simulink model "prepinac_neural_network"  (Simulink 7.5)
settings: Solver=ode45  StartTime=0.0  StopTime=20  FixedStep=1  MaxStep=1  RelTol=1e-3
libraries: neural x26, commutil2 x24, dspmtrx3 x22, simulink x21
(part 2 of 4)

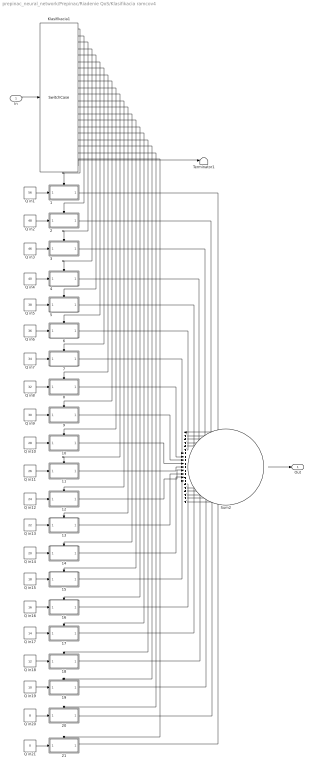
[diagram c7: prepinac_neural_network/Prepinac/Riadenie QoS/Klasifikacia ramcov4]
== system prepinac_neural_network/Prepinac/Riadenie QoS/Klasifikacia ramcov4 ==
  In : Inport  OutDataType=sfix(16)  OutScaling=2^0
  1 : Subsystem  TreatAsAtomicUnit=on
  10 : Subsystem  TreatAsAtomicUnit=on
  11 : Subsystem  TreatAsAtomicUnit=on
  12 : Subsystem  TreatAsAtomicUnit=on
  13 : Subsystem  TreatAsAtomicUnit=on
  14 : Subsystem  TreatAsAtomicUnit=on
  15 : Subsystem  TreatAsAtomicUnit=on
  16 : Subsystem  TreatAsAtomicUnit=on
  17 : Subsystem  TreatAsAtomicUnit=on
  18 : Subsystem  TreatAsAtomicUnit=on
  19 : Subsystem  TreatAsAtomicUnit=on
  2 : Subsystem  TreatAsAtomicUnit=on
  20 : Subsystem  TreatAsAtomicUnit=on
  21 : Subsystem  TreatAsAtomicUnit=on
  3 : Subsystem  TreatAsAtomicUnit=on
  4 : Subsystem  TreatAsAtomicUnit=on
  5 : Subsystem  TreatAsAtomicUnit=on
  6 : Subsystem  TreatAsAtomicUnit=on
  7 : Subsystem  TreatAsAtomicUnit=on
  8 : Subsystem  TreatAsAtomicUnit=on
  9 : Subsystem  TreatAsAtomicUnit=on
  Klasifikacia1 : SwitchCase  CaseConditions={0,8,10,12,14,16,18,20,22,24,26,28,30,32,34,36,38,40,46,48,56}
  Q in1 : Constant  Value=56  VectorParams1D=off  OutDataTypeMode=double  OutDataType=sfix(16)  OutScaling=2^0  OutDataTypeStr=double  SampleTime=-1
  Q in10 : Constant  Value=28  VectorParams1D=off  OutDataTypeMode=double  OutDataType=sfix(16)  OutScaling=2^0  OutDataTypeStr=double  SampleTime=-1
  Q in11 : Constant  Value=26  VectorParams1D=off  OutDataTypeMode=double  OutDataType=sfix(16)  OutScaling=2^0  OutDataTypeStr=double  SampleTime=-1
  Q in12 : Constant  Value=24  VectorParams1D=off  OutDataTypeMode=double  OutDataType=sfix(16)  OutScaling=2^0  OutDataTypeStr=double  SampleTime=-1
  Q in13 : Constant  Value=22  VectorParams1D=off  OutDataTypeMode=double  OutDataType=sfix(16)  OutScaling=2^0  OutDataTypeStr=double  SampleTime=-1
  Q in14 : Constant  Value=20  VectorParams1D=off  OutDataTypeMode=double  OutDataType=sfix(16)  OutScaling=2^0  OutDataTypeStr=double  SampleTime=-1
  Q in15 : Constant  Value=18  VectorParams1D=off  OutDataTypeMode=double  OutDataType=sfix(16)  OutScaling=2^0  OutDataTypeStr=double  SampleTime=-1
  Q in16 : Constant  Value=16  VectorParams1D=off  OutDataTypeMode=double  OutDataType=sfix(16)  OutScaling=2^0  OutDataTypeStr=double  SampleTime=-1
  Q in17 : Constant  Value=14  VectorParams1D=off  OutDataTypeMode=double  OutDataType=sfix(16)  OutScaling=2^0  OutDataTypeStr=double  SampleTime=-1
  Q in18 : Constant  Value=12  VectorParams1D=off  OutDataTypeMode=double  OutDataType=sfix(16)  OutScaling=2^0  OutDataTypeStr=double  SampleTime=-1
  Q in19 : Constant  Value=10  VectorParams1D=off  OutDataTypeMode=double  OutDataType=sfix(16)  OutScaling=2^0  OutDataTypeStr=double  SampleTime=-1
  Q in2 : Constant  Value=48  VectorParams1D=off  OutDataTypeMode=double  OutDataType=sfix(16)  OutScaling=2^0  OutDataTypeStr=double  SampleTime=-1
  Q in20 : Constant  Value=8  VectorParams1D=off  OutDataTypeMode=double  OutDataType=sfix(16)  OutScaling=2^0  OutDataTypeStr=double  SampleTime=-1
  Q in21 : Constant  Value=0  VectorParams1D=off  OutDataTypeMode=double  OutDataType=sfix(16)  OutScaling=2^0  OutDataTypeStr=double  SampleTime=-1
  Q in3 : Constant  Value=46  VectorParams1D=off  OutDataTypeMode=double  OutDataType=sfix(16)  OutScaling=2^0  OutDataTypeStr=double  SampleTime=-1
  Q in4 : Constant  Value=40  VectorParams1D=off  OutDataTypeMode=double  OutDataType=sfix(16)  OutScaling=2^0  OutDataTypeStr=double  SampleTime=-1
  Q in5 : Constant  Value=38  VectorParams1D=off  OutDataTypeMode=double  OutDataType=sfix(16)  OutScaling=2^0  OutDataTypeStr=double  SampleTime=-1
  Q in6 : Constant  Value=36  VectorParams1D=off  OutDataTypeMode=double  OutDataType=sfix(16)  OutScaling=2^0  OutDataTypeStr=double  SampleTime=-1
  Q in7 : Constant  Value=34  VectorParams1D=off  OutDataTypeMode=double  OutDataType=sfix(16)  OutScaling=2^0  OutDataTypeStr=double  SampleTime=-1
  Q in8 : Constant  Value=32  VectorParams1D=off  OutDataTypeMode=double  OutDataType=sfix(16)  OutScaling=2^0  OutDataTypeStr=double  SampleTime=-1
  Q in9 : Constant  Value=30  VectorParams1D=off  OutDataTypeMode=double  OutDataType=sfix(16)  OutScaling=2^0  OutDataTypeStr=double  SampleTime=-1
  Sum2 : Sum  Inputs=|+++++++++++++++++++++  OutDataType=sfix(16)  OutScaling=2^0
  Terminator1 : Terminator
  Out : Outport  OutDataType=sfix(16)  OutScaling=2^0
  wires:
  19/1(Out1) -> Sum2/19
  Klasifikacia1/22 -> Terminator1/1
  Sum2/1 -> Out/1
  Klasifikacia1/21 -> 21/Action
  Klasifikacia1/20 -> 20/Action
  Klasifikacia1/19 -> 19/Action
  Klasifikacia1/18 -> 18/Action
  Klasifikacia1/17 -> 17/Action
  Klasifikacia1/16 -> 16/Action
  Klasifikacia1/15 -> 15/Action
  Klasifikacia1/14 -> 14/Action
  Klasifikacia1/13 -> 13/Action
  Klasifikacia1/12 -> 12/Action
  Klasifikacia1/11 -> 11/Action
  Klasifikacia1/10 -> 10/Action
  Klasifikacia1/9 -> 9/Action
  Klasifikacia1/8 -> 8/Action
  Klasifikacia1/7 -> 7/Action
  Klasifikacia1/6 -> 6/Action
  Klasifikacia1/5 -> 5/Action
  Klasifikacia1/4 -> 4/Action
  Klasifikacia1/3 -> 3/Action
  Klasifikacia1/2 -> 2/Action
  Klasifikacia1/1 -> 1/Action
  In/1 -> Klasifikacia1/1
  9/1(Out1) -> Sum2/9
  10/1(Out1) -> Sum2/10
  11/1(Out1) -> Sum2/11
  12/1(Out1) -> Sum2/12
  13/1(Out1) -> Sum2/13
  14/1(Out1) -> Sum2/14
  15/1(Out1) -> Sum2/15
  16/1(Out1) -> Sum2/16
  17/1(Out1) -> Sum2/17
  18/1(Out1) -> Sum2/18
  20/1(Out1) -> Sum2/20
  21/1(Out1) -> Sum2/21
  8/1(Out1) -> Sum2/8
  7/1(Out1) -> Sum2/7
  6/1(Out1) -> Sum2/6
  5/1(Out1) -> Sum2/5
  Q in21/1 -> 21/1(In1)
  Q in20/1 -> 20/1(In1)
  Q in19/1 -> 19/1(In1)
  Q in18/1 -> 18/1(In1)
  Q in17/1 -> 17/1(In1)
  Q in16/1 -> 16/1(In1)
  Q in15/1 -> 15/1(In1)
  Q in14/1 -> 14/1(In1)
  Q in13/1 -> 13/1(In1)
  Q in12/1 -> 12/1(In1)
  Q in11/1 -> 11/1(In1)
  Q in10/1 -> 10/1(In1)
  Q in9/1 -> 9/1(In1)
  Q in8/1 -> 8/1(In1)
  Q in7/1 -> 7/1(In1)
  Q in6/1 -> 6/1(In1)
  Q in5/1 -> 5/1(In1)
  Q in4/1 -> 4/1(In1)
  Q in3/1 -> 3/1(In1)
  Q in2/1 -> 2/1(In1)
  Q in1/1 -> 1/1(In1)
  4/1(Out1) -> Sum2/4
  3/1(Out1) -> Sum2/3
  2/1(Out1) -> Sum2/2
  1/1(Out1) -> Sum2/1

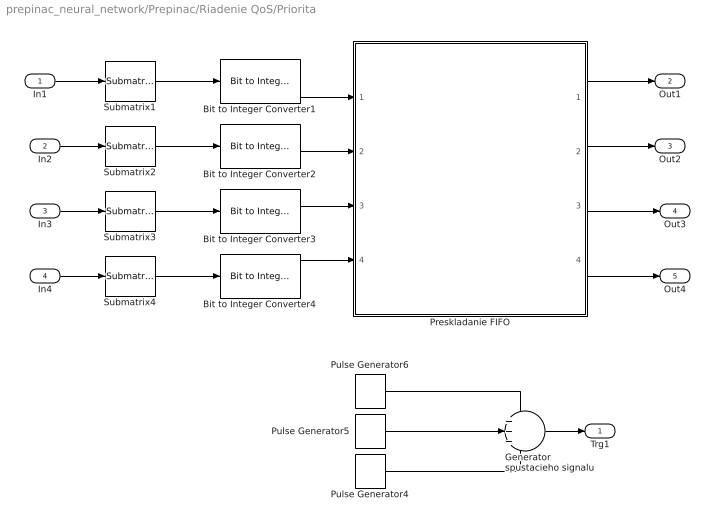
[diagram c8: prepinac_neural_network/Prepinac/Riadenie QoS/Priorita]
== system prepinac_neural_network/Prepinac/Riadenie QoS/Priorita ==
  In1 : Inport  OutDataType=sfix(16)  OutScaling=2^0
  In2 : Inport  Port=2  OutDataType=sfix(16)  OutScaling=2^0
  In3 : Inport  Port=3  OutDataType=sfix(16)  OutScaling=2^0
  In4 : Inport  Port=4  OutDataType=sfix(16)  OutScaling=2^0
  Bit to Integer Converter{1..4} (4 alike) : commutil2/Bit to Integer Converter  nbits=6  bitOrder=MSB first  signedOutputValues=Unsigned  outDtype=double  outDtypeSigned=Inherit via internal rule
  Generator spustacieho signalu : Sum  Inputs=+++  OutDataType=sfix(16)  OutScaling=2^-10
  Preskladanie FIFO : Subsystem
  Pulse Generator4 : DiscretePulseGenerator  PulseType=Time based  Amplitude=3  Period=4  PulseWidth=(1/4)*100  PhaseDelay=4  SampleTime=1
  Pulse Generator5 : DiscretePulseGenerator  PulseType=Time based  Amplitude=2  Period=4  PulseWidth=(1/4)*100  PhaseDelay=3  SampleTime=1
  Pulse Generator6 : DiscretePulseGenerator  PulseType=Time based  Amplitude=1  Period=4  PulseWidth=(1/4)*100  PhaseDelay=2  SampleTime=1
  Submatrix{1..4} (4 alike) : dspmtrx3/Submatrix  RowSpan=All rows  RowStartMode=Index  RowStartIndex=5  RowEndMode=Index  RowEndIndex=12  ColSpan=Range of columns  ColStartMode=Index  ColStartIndex=113  ColEndMode=Index  ColEndIndex=118
  Trg1 : Outport  OutDataType=sfix(16)  OutScaling=2^0
  Out1 : Outport  Port=2  OutDataType=sfix(16)  OutScaling=2^0
  Out2 : Outport  Port=3  OutDataType=sfix(16)  OutScaling=2^0
  Out3 : Outport  Port=4  OutDataType=sfix(16)  OutScaling=2^0
  Out4 : Outport  Port=5  OutDataType=sfix(16)  OutScaling=2^0
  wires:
  In1/1 -> Submatrix1/1
  In2/1 -> Submatrix2/1
  In3/1 -> Submatrix3/1
  In4/1 -> Submatrix4/1
  Submatrix1/1 -> Bit to Integer Converter1/1
  Submatrix2/1 -> Bit to Integer Converter2/1
  Submatrix3/1 -> Bit to Integer Converter3/1
  Submatrix4/1 -> Bit to Integer Converter4/1
  Pulse Generator6/1 -> Generator spustacieho signalu/1
  Pulse Generator5/1 -> Generator spustacieho signalu/2
  Generator spustacieho signalu/1 -> Trg1/1
  Pulse Generator4/1 -> Generator spustacieho signalu/3
  Bit to Integer Converter1/1 -> Preskladanie FIFO/1(In1)
  Bit to Integer Converter3/1 -> Preskladanie FIFO/3(In3)
  Bit to Integer Converter4/1 -> Preskladanie FIFO/4(In4)
  Preskladanie FIFO/1(Out1) -> Out1/1
  Preskladanie FIFO/2(Out2) -> Out2/1
  Preskladanie FIFO/3(Out3) -> Out3/1
  Preskladanie FIFO/4(Out4) -> Out4/1
  Bit to Integer Converter2/1 -> Preskladanie FIFO/2(In2)

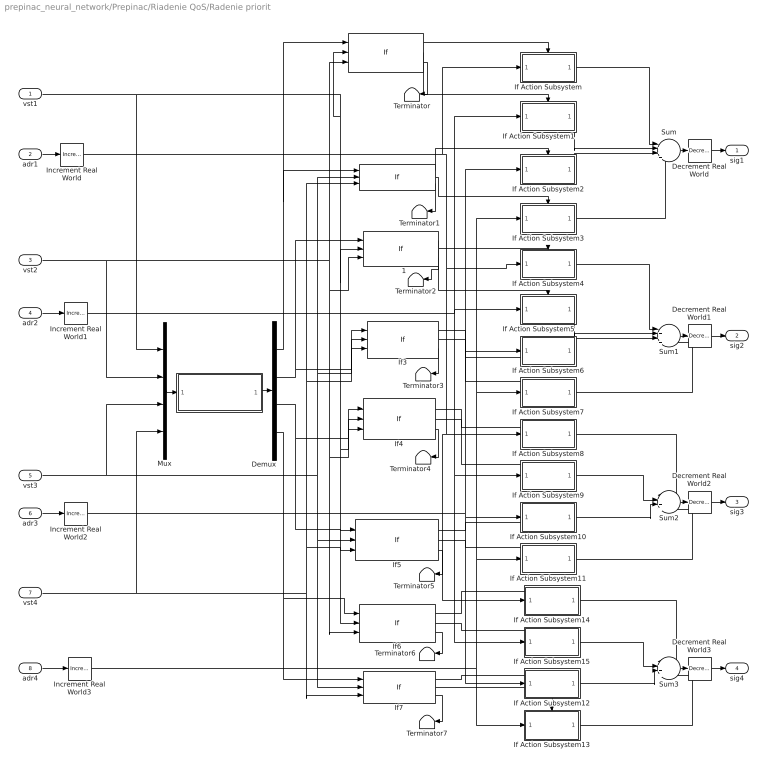
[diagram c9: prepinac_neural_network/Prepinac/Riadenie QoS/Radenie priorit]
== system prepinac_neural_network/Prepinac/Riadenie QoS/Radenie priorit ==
  vst1 : Inport  OutDataType=sfix(16)  OutScaling=2^0
  adr1 : Inport  Port=2  OutDataType=sfix(16)  OutScaling=2^0
  vst2 : Inport  Port=3  OutDataType=sfix(16)  OutScaling=2^0
  adr2 : Inport  Port=4  OutDataType=sfix(16)  OutScaling=2^0
  vst3 : Inport  Port=5  OutDataType=sfix(16)  OutScaling=2^0
  adr3 : Inport  Port=6  OutDataType=sfix(16)  OutScaling=2^0
  vst4 : Inport  Port=7  OutDataType=sfix(16)  OutScaling=2^0
  adr4 : Inport  Port=8  OutDataType=sfix(16)  OutScaling=2^0
  " " : If  NumInputs=3  IfExpression=u1 == u2  ElseIfExpressions=u1 == u3
  "  " : If  NumInputs=3  IfExpression=u1 == u2  ElseIfExpressions=u1 == u3
  "   " : Stateflow chart  TreatAsAtomicUnit=on
  "   1" : If  NumInputs=3  IfExpression=u1 == u2  ElseIfExpressions=u1 == u3
  Decrement Real World{,1..3} (4 alike) : simulink/Additional Math & Discrete/Additional Math: Increment - Decrement/Decrement Real World  SystemSampleTime=-1
  Demux : Demux
  If Action Subsystem : Subsystem  TreatAsAtomicUnit=on
  If Action Subsystem1 : Subsystem  TreatAsAtomicUnit=on
  If Action Subsystem10 : Subsystem  TreatAsAtomicUnit=on
  If Action Subsystem11 : Subsystem  TreatAsAtomicUnit=on
  If Action Subsystem12 : Subsystem  TreatAsAtomicUnit=on
  If Action Subsystem13 : Subsystem  TreatAsAtomicUnit=on
  If Action Subsystem14 : Subsystem  TreatAsAtomicUnit=on
  If Action Subsystem15 : Subsystem  TreatAsAtomicUnit=on
  If Action Subsystem2 : Subsystem  TreatAsAtomicUnit=on
  If Action Subsystem3 : Subsystem  TreatAsAtomicUnit=on
  If Action Subsystem4 : Subsystem  TreatAsAtomicUnit=on
  If Action Subsystem5 : Subsystem  TreatAsAtomicUnit=on
  If Action Subsystem6 : Subsystem  TreatAsAtomicUnit=on
  If Action Subsystem7 : Subsystem  TreatAsAtomicUnit=on
  If Action Subsystem8 : Subsystem  TreatAsAtomicUnit=on
  If Action Subsystem9 : Subsystem  TreatAsAtomicUnit=on
  If{3..7} (5 alike) : If  NumInputs=3  IfExpression=u1 == u2  ElseIfExpressions=u1 == u3
  Increment Real World{,1..3} (4 alike) : simulink/Additional Math & Discrete/Additional Math: Increment - Decrement/Increment Real World  SystemSampleTime=-1
  Mux : Mux
  Sum{,1..3} (4 alike) : Sum  Inputs=|++++  OutDataType=sfix(16)  OutScaling=2^0
  Terminator{,1..7} (8 alike) : Terminator
  sig1 : Outport  OutDataType=sfix(16)  OutScaling=2^0
  sig2 : Outport  Port=2  OutDataType=sfix(16)  OutScaling=2^0
  sig3 : Outport  Port=3  OutDataType=sfix(16)  OutScaling=2^0
  sig4 : Outport  Port=4  OutDataType=sfix(16)  OutScaling=2^0
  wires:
  Mux/1 -> "   "/1(x)
  "   "/1(y) -> Demux/1
  " "/1 -> If Action Subsystem/Action
  " "/2 -> If Action Subsystem1/Action
  adr1/1 -> Increment Real World/1
  adr2/1 -> Increment Real World1/1
  "  "/1 -> If Action Subsystem2/Action
  "  "/2 -> If Action Subsystem3/Action
  adr3/1 -> Increment Real World2/1
  adr4/1 -> Increment Real World3/1
  If Action Subsystem/1(Out1) -> Sum/1
  If Action Subsystem1/1(Out1) -> Sum/2
  If Action Subsystem2/1(Out1) -> Sum/3
  If Action Subsystem3/1(Out1) -> Sum/4
  Sum/1 -> Decrement Real World/1
  Decrement Real World/1 -> sig1/1
  "   1"/1 -> If Action Subsystem4/Action
  "   1"/2 -> If Action Subsystem5/Action
  If3/1 -> If Action Subsystem6/Action
  If3/2 -> If Action Subsystem7/Action
  If Action Subsystem4/1(Out1) -> Sum1/1
  If Action Subsystem5/1(Out1) -> Sum1/2
  If Action Subsystem6/1(Out1) -> Sum1/3
  If Action Subsystem7/1(Out1) -> Sum1/4
  Sum1/1 -> Decrement Real World1/1
  Decrement Real World1/1 -> sig2/1
  If4/1 -> If Action Subsystem8/Action
  If4/2 -> If Action Subsystem9/Action
  If5/1 -> If Action Subsystem10/Action
  If5/2 -> If Action Subsystem11/Action
  If Action Subsystem8/1(Out1) -> Sum2/1
  If Action Subsystem9/1(Out1) -> Sum2/2
  If Action Subsystem10/1(Out1) -> Sum2/3
  If Action Subsystem11/1(Out1) -> Sum2/4
  Sum2/1 -> Decrement Real World2/1
  Decrement Real World2/1 -> sig3/1
  If6/1 -> If Action Subsystem14/Action
  If6/2 -> If Action Subsystem15/Action
  If7/1 -> If Action Subsystem12/Action
  If7/2 -> If Action Subsystem13/Action
  If Action Subsystem14/1(Out1) -> Sum3/1
  If Action Subsystem15/1(Out1) -> Sum3/2
  If Action Subsystem12/1(Out1) -> Sum3/3
  If Action Subsystem13/1(Out1) -> Sum3/4
  Sum3/1 -> Decrement Real World3/1
  Decrement Real World3/1 -> sig4/1
  vst1/1 -> Mux/1, " "/2, "   1"/2, If6/2, If4/2
  vst2/1 -> " "/3, "   1"/3, If6/3, If4/3, Mux/2
  vst3/1 -> "  "/2, If3/2, If5/2, If7/2, Mux/3
  vst4/1 -> "  "/3, If3/3, If5/3, If7/3, Mux/4
  Demux/1 -> " "/1, "  "/1
  Demux/2 -> If3/1, "   1"/1
  Demux/3 -> If4/1, If5/1
  Demux/4 -> If6/1, If7/1
  Increment Real World/1 -> If Action Subsystem/1(In1), If Action Subsystem4/1(In1), If Action Subsystem8/1(In1), If Action Subsystem14/1(In1)
  Increment Real World1/1 -> If Action Subsystem5/1(In1), If Action Subsystem1/1(In1), If Action Subsystem9/1(In1), If Action Subsystem15/1(In1)
  Increment Real World2/1 -> If Action Subsystem2/1(In1), If Action Subsystem6/1(In1), If Action Subsystem10/1(In1), If Action Subsystem12/1(In1)
  Increment Real World3/1 -> If Action Subsystem13/1(In1), If Action Subsystem11/1(In1), If Action Subsystem7/1(In1), If Action Subsystem3/1(In1)
  " "/3 -> Terminator/1
  "  "/3 -> Terminator1/1
  "   1"/3 -> Terminator2/1
  If3/3 -> Terminator3/1
  If4/3 -> Terminator4/1
  If5/3 -> Terminator5/1
  If6/3 -> Terminator6/1
  If7/3 -> Terminator7/1

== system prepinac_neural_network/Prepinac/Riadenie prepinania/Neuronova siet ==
  "x{1}" : Inport  PortDimensions=1  SampleTime=1
  Layer 1 : Subsystem
  Layer 2 : Subsystem
  Process Input 1 : Subsystem
  Process Output 1 : Subsystem
  "y{1}" : Outport  InitialOutput=0
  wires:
  "x{1}"/1 -> Process Input 1/1(x)
  Process Output 1/1(y) -> "y{1}"/1
  Process Input 1/1(p) -> Layer 1/1("p{1}")
  Layer 1/1("a{1}") -> [feedback1]
  [feedback1] -> Layer 2/1("a{1} ")
  Layer 2/1("a{2}") -> Process Output 1/1(a)

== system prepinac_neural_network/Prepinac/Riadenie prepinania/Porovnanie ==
  Vstup : Inport  OutDataType=sfix(16)  OutScaling=2^0
  Abs : Abs
  Porovnani4 : simulink/Logic and Bit Operations/Compare To Constant  SystemSampleTime=-1  relop=>=  const=0.1  LogicOutDataTypeMode=boolean  ZeroCross=off
  Vystup : Outport  OutDataType=sfix(16)  OutScaling=2^0
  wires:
  Abs/1 -> Porovnani4/1
  Porovnani4/1 -> Vystup/1
  Vstup/1 -> Abs/1

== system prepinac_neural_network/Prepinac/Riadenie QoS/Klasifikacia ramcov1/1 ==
  In1 : Inport  OutDataType=sfix(16)  OutScaling=2^0
  Action Port : ActionPort  ActionType=case
  Out1 : Outport  OutDataType=sfix(16)  OutScaling=2^0
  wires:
  In1/1 -> Out1/1

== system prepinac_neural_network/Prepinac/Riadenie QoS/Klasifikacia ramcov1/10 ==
  In1 : Inport  OutDataType=sfix(16)  OutScaling=2^0
  Action Port : ActionPort  ActionType=case
  Out1 : Outport  OutDataType=sfix(16)  OutScaling=2^0
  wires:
  In1/1 -> Out1/1

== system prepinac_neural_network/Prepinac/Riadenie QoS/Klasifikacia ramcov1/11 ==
  In1 : Inport  OutDataType=sfix(16)  OutScaling=2^0
  Action Port : ActionPort  ActionType=case
  Out1 : Outport  OutDataType=sfix(16)  OutScaling=2^0
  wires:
  In1/1 -> Out1/1

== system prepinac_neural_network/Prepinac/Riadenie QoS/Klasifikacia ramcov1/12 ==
  In1 : Inport  OutDataType=sfix(16)  OutScaling=2^0
  Action Port : ActionPort  ActionType=case
  Out1 : Outport  OutDataType=sfix(16)  OutScaling=2^0
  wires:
  In1/1 -> Out1/1

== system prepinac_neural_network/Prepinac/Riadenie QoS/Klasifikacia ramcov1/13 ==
  In1 : Inport  OutDataType=sfix(16)  OutScaling=2^0
  Action Port : ActionPort  ActionType=case
  Out1 : Outport  OutDataType=sfix(16)  OutScaling=2^0
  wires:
  In1/1 -> Out1/1

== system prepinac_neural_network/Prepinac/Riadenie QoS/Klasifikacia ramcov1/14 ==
  In1 : Inport  OutDataType=sfix(16)  OutScaling=2^0
  Action Port : ActionPort  ActionType=case
  Out1 : Outport  OutDataType=sfix(16)  OutScaling=2^0
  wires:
  In1/1 -> Out1/1

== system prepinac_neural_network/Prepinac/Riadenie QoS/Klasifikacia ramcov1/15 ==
  In1 : Inport  OutDataType=sfix(16)  OutScaling=2^0
  Action Port : ActionPort  ActionType=case
  Out1 : Outport  OutDataType=sfix(16)  OutScaling=2^0
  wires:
  In1/1 -> Out1/1

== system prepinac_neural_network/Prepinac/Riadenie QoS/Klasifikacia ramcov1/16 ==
  In1 : Inport  OutDataType=sfix(16)  OutScaling=2^0
  Action Port : ActionPort  ActionType=case
  Out1 : Outport  OutDataType=sfix(16)  OutScaling=2^0
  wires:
  In1/1 -> Out1/1

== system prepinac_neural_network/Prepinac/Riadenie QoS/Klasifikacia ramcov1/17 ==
  In1 : Inport  OutDataType=sfix(16)  OutScaling=2^0
  Action Port : ActionPort  ActionType=case
  Out1 : Outport  OutDataType=sfix(16)  OutScaling=2^0
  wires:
  In1/1 -> Out1/1

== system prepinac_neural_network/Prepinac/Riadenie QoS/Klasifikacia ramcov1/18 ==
  In1 : Inport  OutDataType=sfix(16)  OutScaling=2^0
  Action Port : ActionPort  ActionType=case
  Out1 : Outport  OutDataType=sfix(16)  OutScaling=2^0
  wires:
  In1/1 -> Out1/1

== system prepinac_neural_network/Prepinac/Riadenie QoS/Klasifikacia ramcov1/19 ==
  In1 : Inport  OutDataType=sfix(16)  OutScaling=2^0
  Action Port : ActionPort  ActionType=case
  Out1 : Outport  OutDataType=sfix(16)  OutScaling=2^0
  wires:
  In1/1 -> Out1/1

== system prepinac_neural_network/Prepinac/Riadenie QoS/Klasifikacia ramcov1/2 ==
  In1 : Inport  OutDataType=sfix(16)  OutScaling=2^0
  Action Port : ActionPort  ActionType=case
  Out1 : Outport  OutDataType=sfix(16)  OutScaling=2^0
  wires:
  In1/1 -> Out1/1

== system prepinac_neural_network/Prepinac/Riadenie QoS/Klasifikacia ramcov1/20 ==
  In1 : Inport  OutDataType=sfix(16)  OutScaling=2^0
  Action Port : ActionPort  ActionType=case
  Out1 : Outport  OutDataType=sfix(16)  OutScaling=2^0
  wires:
  In1/1 -> Out1/1

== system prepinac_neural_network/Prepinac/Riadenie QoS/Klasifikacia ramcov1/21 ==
  In1 : Inport  OutDataType=sfix(16)  OutScaling=2^0
  Action Port : ActionPort  ActionType=case
  Out1 : Outport  OutDataType=sfix(16)  OutScaling=2^0
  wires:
  In1/1 -> Out1/1

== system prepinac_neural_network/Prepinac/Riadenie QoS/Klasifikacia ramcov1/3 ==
  In1 : Inport  OutDataType=sfix(16)  OutScaling=2^0
  Action Port : ActionPort  ActionType=case
  Out1 : Outport  OutDataType=sfix(16)  OutScaling=2^0
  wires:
  In1/1 -> Out1/1

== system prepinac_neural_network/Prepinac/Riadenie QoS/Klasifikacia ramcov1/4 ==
  In1 : Inport  OutDataType=sfix(16)  OutScaling=2^0
  Action Port : ActionPort  ActionType=case
  Out1 : Outport  OutDataType=sfix(16)  OutScaling=2^0
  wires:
  In1/1 -> Out1/1

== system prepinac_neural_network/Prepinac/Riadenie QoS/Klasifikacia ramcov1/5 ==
  In1 : Inport  OutDataType=sfix(16)  OutScaling=2^0
  Action Port : ActionPort  ActionType=case
  Out1 : Outport  OutDataType=sfix(16)  OutScaling=2^0
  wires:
  In1/1 -> Out1/1

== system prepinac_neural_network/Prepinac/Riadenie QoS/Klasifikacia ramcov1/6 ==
  In1 : Inport  OutDataType=sfix(16)  OutScaling=2^0
  Action Port : ActionPort  ActionType=case
  Out1 : Outport  OutDataType=sfix(16)  OutScaling=2^0
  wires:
  In1/1 -> Out1/1

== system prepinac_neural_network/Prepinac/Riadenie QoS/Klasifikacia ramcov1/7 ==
  In1 : Inport  OutDataType=sfix(16)  OutScaling=2^0
  Action Port : ActionPort  ActionType=case
  Out1 : Outport  OutDataType=sfix(16)  OutScaling=2^0
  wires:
  In1/1 -> Out1/1

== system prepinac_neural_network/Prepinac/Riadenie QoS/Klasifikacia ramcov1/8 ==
  In1 : Inport  OutDataType=sfix(16)  OutScaling=2^0
  Action Port : ActionPort  ActionType=case
  Out1 : Outport  OutDataType=sfix(16)  OutScaling=2^0
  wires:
  In1/1 -> Out1/1

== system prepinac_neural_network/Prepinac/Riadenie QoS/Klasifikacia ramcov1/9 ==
  In1 : Inport  OutDataType=sfix(16)  OutScaling=2^0
  Action Port : ActionPort  ActionType=case
  Out1 : Outport  OutDataType=sfix(16)  OutScaling=2^0
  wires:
  In1/1 -> Out1/1

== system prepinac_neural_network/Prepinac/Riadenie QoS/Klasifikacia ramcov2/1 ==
  In1 : Inport  OutDataType=sfix(16)  OutScaling=2^0
  Action Port : ActionPort  ActionType=case
  Out1 : Outport  OutDataType=sfix(16)  OutScaling=2^0
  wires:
  In1/1 -> Out1/1

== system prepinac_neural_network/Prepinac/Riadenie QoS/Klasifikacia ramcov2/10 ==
  In1 : Inport  OutDataType=sfix(16)  OutScaling=2^0
  Action Port : ActionPort  ActionType=case
  Out1 : Outport  OutDataType=sfix(16)  OutScaling=2^0
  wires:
  In1/1 -> Out1/1

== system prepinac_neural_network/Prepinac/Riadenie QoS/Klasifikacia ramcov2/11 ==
  In1 : Inport  OutDataType=sfix(16)  OutScaling=2^0
  Action Port : ActionPort  ActionType=case
  Out1 : Outport  OutDataType=sfix(16)  OutScaling=2^0
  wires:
  In1/1 -> Out1/1

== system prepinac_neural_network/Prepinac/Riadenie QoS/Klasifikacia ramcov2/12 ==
  In1 : Inport  OutDataType=sfix(16)  OutScaling=2^0
  Action Port : ActionPort  ActionType=case
  Out1 : Outport  OutDataType=sfix(16)  OutScaling=2^0
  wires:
  In1/1 -> Out1/1

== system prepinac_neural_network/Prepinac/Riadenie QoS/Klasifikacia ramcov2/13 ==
  In1 : Inport  OutDataType=sfix(16)  OutScaling=2^0
  Action Port : ActionPort  ActionType=case
  Out1 : Outport  OutDataType=sfix(16)  OutScaling=2^0
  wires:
  In1/1 -> Out1/1

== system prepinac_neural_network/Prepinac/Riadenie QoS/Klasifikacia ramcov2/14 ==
  In1 : Inport  OutDataType=sfix(16)  OutScaling=2^0
  Action Port : ActionPort  ActionType=case
  Out1 : Outport  OutDataType=sfix(16)  OutScaling=2^0
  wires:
  In1/1 -> Out1/1

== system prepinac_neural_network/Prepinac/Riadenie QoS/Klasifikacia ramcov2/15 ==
  In1 : Inport  OutDataType=sfix(16)  OutScaling=2^0
  Action Port : ActionPort  ActionType=case
  Out1 : Outport  OutDataType=sfix(16)  OutScaling=2^0
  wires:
  In1/1 -> Out1/1

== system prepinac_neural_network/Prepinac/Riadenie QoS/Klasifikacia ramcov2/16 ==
  In1 : Inport  OutDataType=sfix(16)  OutScaling=2^0
  Action Port : ActionPort  ActionType=case
  Out1 : Outport  OutDataType=sfix(16)  OutScaling=2^0
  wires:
  In1/1 -> Out1/1

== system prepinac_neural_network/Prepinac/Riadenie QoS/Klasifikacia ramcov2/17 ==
  In1 : Inport  OutDataType=sfix(16)  OutScaling=2^0
  Action Port : ActionPort  ActionType=case
  Out1 : Outport  OutDataType=sfix(16)  OutScaling=2^0
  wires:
  In1/1 -> Out1/1

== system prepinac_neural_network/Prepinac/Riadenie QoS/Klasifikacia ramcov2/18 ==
  In1 : Inport  OutDataType=sfix(16)  OutScaling=2^0
  Action Port : ActionPort  ActionType=case
  Out1 : Outport  OutDataType=sfix(16)  OutScaling=2^0
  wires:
  In1/1 -> Out1/1

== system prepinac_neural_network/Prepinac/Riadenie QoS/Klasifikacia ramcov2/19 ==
  In1 : Inport  OutDataType=sfix(16)  OutScaling=2^0
  Action Port : ActionPort  ActionType=case
  Out1 : Outport  OutDataType=sfix(16)  OutScaling=2^0
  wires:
  In1/1 -> Out1/1

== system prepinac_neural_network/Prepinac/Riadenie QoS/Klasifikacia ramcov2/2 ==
  In1 : Inport  OutDataType=sfix(16)  OutScaling=2^0
  Action Port : ActionPort  ActionType=case
  Out1 : Outport  OutDataType=sfix(16)  OutScaling=2^0
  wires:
  In1/1 -> Out1/1

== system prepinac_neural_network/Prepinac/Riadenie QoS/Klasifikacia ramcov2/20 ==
  In1 : Inport  OutDataType=sfix(16)  OutScaling=2^0
  Action Port : ActionPort  ActionType=case
  Out1 : Outport  OutDataType=sfix(16)  OutScaling=2^0
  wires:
  In1/1 -> Out1/1

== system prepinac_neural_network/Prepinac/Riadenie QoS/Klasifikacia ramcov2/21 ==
  In1 : Inport  OutDataType=sfix(16)  OutScaling=2^0
  Action Port : ActionPort  ActionType=case
  Out1 : Outport  OutDataType=sfix(16)  OutScaling=2^0
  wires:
  In1/1 -> Out1/1

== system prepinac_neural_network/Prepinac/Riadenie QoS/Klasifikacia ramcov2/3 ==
  In1 : Inport  OutDataType=sfix(16)  OutScaling=2^0
  Action Port : ActionPort  ActionType=case
  Out1 : Outport  OutDataType=sfix(16)  OutScaling=2^0
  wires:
  In1/1 -> Out1/1

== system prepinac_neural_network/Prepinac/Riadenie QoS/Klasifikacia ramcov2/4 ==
  In1 : Inport  OutDataType=sfix(16)  OutScaling=2^0
  Action Port : ActionPort  ActionType=case
  Out1 : Outport  OutDataType=sfix(16)  OutScaling=2^0
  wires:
  In1/1 -> Out1/1

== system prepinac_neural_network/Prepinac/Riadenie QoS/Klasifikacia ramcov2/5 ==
  In1 : Inport  OutDataType=sfix(16)  OutScaling=2^0
  Action Port : ActionPort  ActionType=case
  Out1 : Outport  OutDataType=sfix(16)  OutScaling=2^0
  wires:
  In1/1 -> Out1/1

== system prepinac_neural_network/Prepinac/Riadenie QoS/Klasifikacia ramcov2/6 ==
  In1 : Inport  OutDataType=sfix(16)  OutScaling=2^0
  Action Port : ActionPort  ActionType=case
  Out1 : Outport  OutDataType=sfix(16)  OutScaling=2^0
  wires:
  In1/1 -> Out1/1

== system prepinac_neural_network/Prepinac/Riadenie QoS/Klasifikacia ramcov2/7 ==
  In1 : Inport  OutDataType=sfix(16)  OutScaling=2^0
  Action Port : ActionPort  ActionType=case
  Out1 : Outport  OutDataType=sfix(16)  OutScaling=2^0
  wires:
  In1/1 -> Out1/1

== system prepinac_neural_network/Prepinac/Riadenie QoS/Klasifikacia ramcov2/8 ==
  In1 : Inport  OutDataType=sfix(16)  OutScaling=2^0
  Action Port : ActionPort  ActionType=case
  Out1 : Outport  OutDataType=sfix(16)  OutScaling=2^0
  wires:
  In1/1 -> Out1/1

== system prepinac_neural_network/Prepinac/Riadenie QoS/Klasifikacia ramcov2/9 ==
  In1 : Inport  OutDataType=sfix(16)  OutScaling=2^0
  Action Port : ActionPort  ActionType=case
  Out1 : Outport  OutDataType=sfix(16)  OutScaling=2^0
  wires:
  In1/1 -> Out1/1

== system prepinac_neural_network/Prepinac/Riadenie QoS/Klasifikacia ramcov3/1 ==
  In1 : Inport  OutDataType=sfix(16)  OutScaling=2^0
  Action Port : ActionPort  ActionType=case
  Out1 : Outport  OutDataType=sfix(16)  OutScaling=2^0
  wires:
  In1/1 -> Out1/1

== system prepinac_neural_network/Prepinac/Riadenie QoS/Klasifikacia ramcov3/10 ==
  In1 : Inport  OutDataType=sfix(16)  OutScaling=2^0
  Action Port : ActionPort  ActionType=case
  Out1 : Outport  OutDataType=sfix(16)  OutScaling=2^0
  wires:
  In1/1 -> Out1/1

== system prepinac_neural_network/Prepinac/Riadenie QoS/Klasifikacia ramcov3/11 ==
  In1 : Inport  OutDataType=sfix(16)  OutScaling=2^0
  Action Port : ActionPort  ActionType=case
  Out1 : Outport  OutDataType=sfix(16)  OutScaling=2^0
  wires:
  In1/1 -> Out1/1

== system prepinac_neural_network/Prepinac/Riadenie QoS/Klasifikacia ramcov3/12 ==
  In1 : Inport  OutDataType=sfix(16)  OutScaling=2^0
  Action Port : ActionPort  ActionType=case
  Out1 : Outport  OutDataType=sfix(16)  OutScaling=2^0
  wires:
  In1/1 -> Out1/1

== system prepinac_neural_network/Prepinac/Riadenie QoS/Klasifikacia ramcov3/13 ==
  In1 : Inport  OutDataType=sfix(16)  OutScaling=2^0
  Action Port : ActionPort  ActionType=case
  Out1 : Outport  OutDataType=sfix(16)  OutScaling=2^0
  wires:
  In1/1 -> Out1/1

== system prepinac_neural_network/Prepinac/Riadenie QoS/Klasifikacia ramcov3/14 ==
  In1 : Inport  OutDataType=sfix(16)  OutScaling=2^0
  Action Port : ActionPort  ActionType=case
  Out1 : Outport  OutDataType=sfix(16)  OutScaling=2^0
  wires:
  In1/1 -> Out1/1

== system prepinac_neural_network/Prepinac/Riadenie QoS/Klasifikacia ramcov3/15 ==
  In1 : Inport  OutDataType=sfix(16)  OutScaling=2^0
  Action Port : ActionPort  ActionType=case
  Out1 : Outport  OutDataType=sfix(16)  OutScaling=2^0
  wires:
  In1/1 -> Out1/1

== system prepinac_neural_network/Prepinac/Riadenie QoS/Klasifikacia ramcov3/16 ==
  In1 : Inport  OutDataType=sfix(16)  OutScaling=2^0
  Action Port : ActionPort  ActionType=case
  Out1 : Outport  OutDataType=sfix(16)  OutScaling=2^0
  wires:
  In1/1 -> Out1/1

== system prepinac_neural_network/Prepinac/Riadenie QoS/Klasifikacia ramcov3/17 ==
  In1 : Inport  OutDataType=sfix(16)  OutScaling=2^0
  Action Port : ActionPort  ActionType=case
  Out1 : Outport  OutDataType=sfix(16)  OutScaling=2^0
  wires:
  In1/1 -> Out1/1

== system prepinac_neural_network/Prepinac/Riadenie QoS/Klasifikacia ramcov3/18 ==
  In1 : Inport  OutDataType=sfix(16)  OutScaling=2^0
  Action Port : ActionPort  ActionType=case
  Out1 : Outport  OutDataType=sfix(16)  OutScaling=2^0
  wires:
  In1/1 -> Out1/1

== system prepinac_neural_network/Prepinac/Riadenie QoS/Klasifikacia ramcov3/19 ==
  In1 : Inport  OutDataType=sfix(16)  OutScaling=2^0
  Action Port : ActionPort  ActionType=case
  Out1 : Outport  OutDataType=sfix(16)  OutScaling=2^0
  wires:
  In1/1 -> Out1/1

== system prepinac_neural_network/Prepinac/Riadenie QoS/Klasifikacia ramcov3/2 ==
  In1 : Inport  OutDataType=sfix(16)  OutScaling=2^0
  Action Port : ActionPort  ActionType=case
  Out1 : Outport  OutDataType=sfix(16)  OutScaling=2^0
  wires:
  In1/1 -> Out1/1

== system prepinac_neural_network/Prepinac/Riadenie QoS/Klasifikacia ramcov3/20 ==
  In1 : Inport  OutDataType=sfix(16)  OutScaling=2^0
  Action Port : ActionPort  ActionType=case
  Out1 : Outport  OutDataType=sfix(16)  OutScaling=2^0
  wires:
  In1/1 -> Out1/1

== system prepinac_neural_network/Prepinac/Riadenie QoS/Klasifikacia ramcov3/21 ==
  In1 : Inport  OutDataType=sfix(16)  OutScaling=2^0
  Action Port : ActionPort  ActionType=case
  Out1 : Outport  OutDataType=sfix(16)  OutScaling=2^0
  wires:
  In1/1 -> Out1/1

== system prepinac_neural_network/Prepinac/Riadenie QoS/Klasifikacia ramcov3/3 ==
  In1 : Inport  OutDataType=sfix(16)  OutScaling=2^0
  Action Port : ActionPort  ActionType=case
  Out1 : Outport  OutDataType=sfix(16)  OutScaling=2^0
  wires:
  In1/1 -> Out1/1

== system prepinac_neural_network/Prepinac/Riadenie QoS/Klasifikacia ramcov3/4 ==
  In1 : Inport  OutDataType=sfix(16)  OutScaling=2^0
  Action Port : ActionPort  ActionType=case
  Out1 : Outport  OutDataType=sfix(16)  OutScaling=2^0
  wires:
  In1/1 -> Out1/1

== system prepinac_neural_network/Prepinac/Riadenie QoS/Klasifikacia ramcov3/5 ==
  In1 : Inport  OutDataType=sfix(16)  OutScaling=2^0
  Action Port : ActionPort  ActionType=case
  Out1 : Outport  OutDataType=sfix(16)  OutScaling=2^0
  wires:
  In1/1 -> Out1/1

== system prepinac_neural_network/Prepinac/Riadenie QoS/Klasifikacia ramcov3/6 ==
  In1 : Inport  OutDataType=sfix(16)  OutScaling=2^0
  Action Port : ActionPort  ActionType=case
  Out1 : Outport  OutDataType=sfix(16)  OutScaling=2^0
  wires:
  In1/1 -> Out1/1

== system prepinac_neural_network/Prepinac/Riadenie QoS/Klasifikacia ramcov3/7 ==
  In1 : Inport  OutDataType=sfix(16)  OutScaling=2^0
  Action Port : ActionPort  ActionType=case
  Out1 : Outport  OutDataType=sfix(16)  OutScaling=2^0
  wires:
  In1/1 -> Out1/1

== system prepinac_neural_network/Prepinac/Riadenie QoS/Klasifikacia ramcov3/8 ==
  In1 : Inport  OutDataType=sfix(16)  OutScaling=2^0
  Action Port : ActionPort  ActionType=case
  Out1 : Outport  OutDataType=sfix(16)  OutScaling=2^0
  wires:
  In1/1 -> Out1/1

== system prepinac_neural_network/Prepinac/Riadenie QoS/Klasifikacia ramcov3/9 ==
  In1 : Inport  OutDataType=sfix(16)  OutScaling=2^0
  Action Port : ActionPort  ActionType=case
  Out1 : Outport  OutDataType=sfix(16)  OutScaling=2^0
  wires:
  In1/1 -> Out1/1

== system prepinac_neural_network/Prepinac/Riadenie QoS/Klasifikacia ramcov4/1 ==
  In1 : Inport  OutDataType=sfix(16)  OutScaling=2^0
  Action Port : ActionPort  ActionType=case
  Out1 : Outport  OutDataType=sfix(16)  OutScaling=2^0
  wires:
  In1/1 -> Out1/1

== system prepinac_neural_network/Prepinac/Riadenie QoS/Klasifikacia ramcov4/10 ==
  In1 : Inport  OutDataType=sfix(16)  OutScaling=2^0
  Action Port : ActionPort  ActionType=case
  Out1 : Outport  OutDataType=sfix(16)  OutScaling=2^0
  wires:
  In1/1 -> Out1/1

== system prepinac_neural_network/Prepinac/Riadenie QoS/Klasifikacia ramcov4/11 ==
  In1 : Inport  OutDataType=sfix(16)  OutScaling=2^0
  Action Port : ActionPort  ActionType=case
  Out1 : Outport  OutDataType=sfix(16)  OutScaling=2^0
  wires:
  In1/1 -> Out1/1

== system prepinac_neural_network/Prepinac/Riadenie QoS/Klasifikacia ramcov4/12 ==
  In1 : Inport  OutDataType=sfix(16)  OutScaling=2^0
  Action Port : ActionPort  ActionType=case
  Out1 : Outport  OutDataType=sfix(16)  OutScaling=2^0
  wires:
  In1/1 -> Out1/1

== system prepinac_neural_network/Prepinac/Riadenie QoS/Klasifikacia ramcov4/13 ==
  In1 : Inport  OutDataType=sfix(16)  OutScaling=2^0
  Action Port : ActionPort  ActionType=case
  Out1 : Outport  OutDataType=sfix(16)  OutScaling=2^0
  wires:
  In1/1 -> Out1/1

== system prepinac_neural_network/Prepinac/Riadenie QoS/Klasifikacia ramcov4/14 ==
  In1 : Inport  OutDataType=sfix(16)  OutScaling=2^0
  Action Port : ActionPort  ActionType=case
  Out1 : Outport  OutDataType=sfix(16)  OutScaling=2^0
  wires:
  In1/1 -> Out1/1

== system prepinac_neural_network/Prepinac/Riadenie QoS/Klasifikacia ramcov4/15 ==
  In1 : Inport  OutDataType=sfix(16)  OutScaling=2^0
  Action Port : ActionPort  ActionType=case
  Out1 : Outport  OutDataType=sfix(16)  OutScaling=2^0
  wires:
  In1/1 -> Out1/1

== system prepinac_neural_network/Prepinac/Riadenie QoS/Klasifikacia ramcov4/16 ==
  In1 : Inport  OutDataType=sfix(16)  OutScaling=2^0
  Action Port : ActionPort  ActionType=case
  Out1 : Outport  OutDataType=sfix(16)  OutScaling=2^0
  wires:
  In1/1 -> Out1/1

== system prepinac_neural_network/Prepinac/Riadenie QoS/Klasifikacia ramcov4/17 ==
  In1 : Inport  OutDataType=sfix(16)  OutScaling=2^0
  Action Port : ActionPort  ActionType=case
  Out1 : Outport  OutDataType=sfix(16)  OutScaling=2^0
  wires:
  In1/1 -> Out1/1

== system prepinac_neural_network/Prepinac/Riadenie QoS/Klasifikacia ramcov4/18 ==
  In1 : Inport  OutDataType=sfix(16)  OutScaling=2^0
  Action Port : ActionPort  ActionType=case
  Out1 : Outport  OutDataType=sfix(16)  OutScaling=2^0
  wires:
  In1/1 -> Out1/1

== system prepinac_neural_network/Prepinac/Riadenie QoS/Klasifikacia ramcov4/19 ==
  In1 : Inport  OutDataType=sfix(16)  OutScaling=2^0
  Action Port : ActionPort  ActionType=case
  Out1 : Outport  OutDataType=sfix(16)  OutScaling=2^0
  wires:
  In1/1 -> Out1/1

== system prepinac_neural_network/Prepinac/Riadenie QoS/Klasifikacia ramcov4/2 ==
  In1 : Inport  OutDataType=sfix(16)  OutScaling=2^0
  Action Port : ActionPort  ActionType=case
  Out1 : Outport  OutDataType=sfix(16)  OutScaling=2^0
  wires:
  In1/1 -> Out1/1

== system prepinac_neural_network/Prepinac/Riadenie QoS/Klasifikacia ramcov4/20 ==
  In1 : Inport  OutDataType=sfix(16)  OutScaling=2^0
  Action Port : ActionPort  ActionType=case
  Out1 : Outport  OutDataType=sfix(16)  OutScaling=2^0
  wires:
  In1/1 -> Out1/1

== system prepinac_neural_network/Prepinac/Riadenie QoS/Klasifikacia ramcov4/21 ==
  In1 : Inport  OutDataType=sfix(16)  OutScaling=2^0
  Action Port : ActionPort  ActionType=case
  Out1 : Outport  OutDataType=sfix(16)  OutScaling=2^0
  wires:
  In1/1 -> Out1/1

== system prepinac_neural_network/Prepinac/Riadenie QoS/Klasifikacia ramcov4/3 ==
  In1 : Inport  OutDataType=sfix(16)  OutScaling=2^0
  Action Port : ActionPort  ActionType=case
  Out1 : Outport  OutDataType=sfix(16)  OutScaling=2^0
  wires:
  In1/1 -> Out1/1

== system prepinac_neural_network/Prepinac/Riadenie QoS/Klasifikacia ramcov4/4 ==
  In1 : Inport  OutDataType=sfix(16)  OutScaling=2^0
  Action Port : ActionPort  ActionType=case
  Out1 : Outport  OutDataType=sfix(16)  OutScaling=2^0
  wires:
  In1/1 -> Out1/1

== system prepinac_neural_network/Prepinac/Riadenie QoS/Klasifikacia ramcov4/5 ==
  In1 : Inport  OutDataType=sfix(16)  OutScaling=2^0
  Action Port : ActionPort  ActionType=case
  Out1 : Outport  OutDataType=sfix(16)  OutScaling=2^0
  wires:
  In1/1 -> Out1/1

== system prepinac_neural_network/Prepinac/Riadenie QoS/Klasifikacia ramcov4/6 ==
  In1 : Inport  OutDataType=sfix(16)  OutScaling=2^0
  Action Port : ActionPort  ActionType=case
  Out1 : Outport  OutDataType=sfix(16)  OutScaling=2^0
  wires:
  In1/1 -> Out1/1

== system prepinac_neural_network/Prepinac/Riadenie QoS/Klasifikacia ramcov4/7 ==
  In1 : Inport  OutDataType=sfix(16)  OutScaling=2^0
  Action Port : ActionPort  ActionType=case
  Out1 : Outport  OutDataType=sfix(16)  OutScaling=2^0
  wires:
  In1/1 -> Out1/1

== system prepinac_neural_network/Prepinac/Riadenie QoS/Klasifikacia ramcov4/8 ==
  In1 : Inport  OutDataType=sfix(16)  OutScaling=2^0
  Action Port : ActionPort  ActionType=case
  Out1 : Outport  OutDataType=sfix(16)  OutScaling=2^0
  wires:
  In1/1 -> Out1/1

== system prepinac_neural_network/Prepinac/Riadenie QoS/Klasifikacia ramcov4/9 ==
  In1 : Inport  OutDataType=sfix(16)  OutScaling=2^0
  Action Port : ActionPort  ActionType=case
  Out1 : Outport  OutDataType=sfix(16)  OutScaling=2^0
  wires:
  In1/1 -> Out1/1
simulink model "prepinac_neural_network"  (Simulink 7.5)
settings: Solver=ode45  StartTime=0.0  StopTime=20  FixedStep=1  MaxStep=1  RelTol=1e-3
libraries: neural x26, commutil2 x24, dspmtrx3 x22, simulink x21
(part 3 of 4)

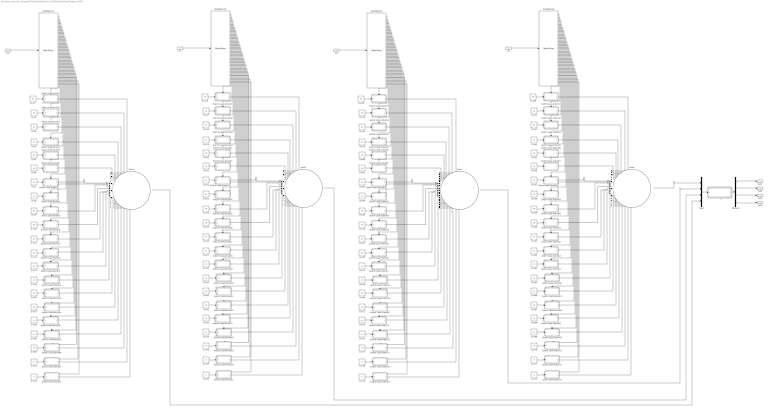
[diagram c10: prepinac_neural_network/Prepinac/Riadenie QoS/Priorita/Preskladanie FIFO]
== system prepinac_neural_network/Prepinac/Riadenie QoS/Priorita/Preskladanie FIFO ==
  In1 : Inport  OutDataType=sfix(16)  OutScaling=2^0
  In2 : Inport  Port=2  OutDataType=sfix(16)  OutScaling=2^0
  In3 : Inport  Port=3  OutDataType=sfix(16)  OutScaling=2^0
  In4 : Inport  Port=4  OutDataType=sfix(16)  OutScaling=2^0
  "     1" : Stateflow chart  TreatAsAtomicUnit=on
  Demux1 : Demux
  Klasifikacia{1..4} (4 alike) : SwitchCase  CaseConditions={0,8,10,12,14,16,18,20,22,24,26,28,30,32,34,36,38,40,46,48,56}  ShowDefaultCase=off
  Mux1 : Mux
  Q in{1,16,43,50} (4 alike) : Constant  Value=56  VectorParams1D=off  OutDataTypeMode=double  OutDataType=sfix(16)  OutScaling=2^0  OutDataTypeStr=double  SampleTime=-1
  Q in{10,25,44,60} (4 alike) : Constant  Value=28  VectorParams1D=off  OutDataTypeMode=double  OutDataType=sfix(16)  OutScaling=2^0  OutDataTypeStr=double  SampleTime=-1
  Q in{11,26,45,61} (4 alike) : Constant  Value=26  VectorParams1D=off  OutDataTypeMode=double  OutDataType=sfix(16)  OutScaling=2^0  OutDataTypeStr=double  SampleTime=-1
  Q in{12,27,46,62} (4 alike) : Constant  Value=24  VectorParams1D=off  OutDataTypeMode=double  OutDataType=sfix(16)  OutScaling=2^0  OutDataTypeStr=double  SampleTime=-1
  Q in{13,28,47,63} (4 alike) : Constant  Value=22  VectorParams1D=off  OutDataTypeMode=double  OutDataType=sfix(16)  OutScaling=2^0  OutDataTypeStr=double  SampleTime=-1
  Q in{14,29,48,64} (4 alike) : Constant  Value=20  VectorParams1D=off  OutDataTypeMode=double  OutDataType=sfix(16)  OutScaling=2^0  OutDataTypeStr=double  SampleTime=-1
  Q in{15,30,49,66} (4 alike) : Constant  Value=18  VectorParams1D=off  OutDataTypeMode=double  OutDataType=sfix(16)  OutScaling=2^0  OutDataTypeStr=double  SampleTime=-1
  Q in{2,17,51,54} (4 alike) : Constant  Value=48  VectorParams1D=off  OutDataTypeMode=double  OutDataType=sfix(16)  OutScaling=2^0  OutDataTypeStr=double  SampleTime=-1
  Q in{3,18,52,65} (4 alike) : Constant  Value=46  VectorParams1D=off  OutDataTypeMode=double  OutDataType=sfix(16)  OutScaling=2^0  OutDataTypeStr=double  SampleTime=-1
  Q in{4,19,53,76} (4 alike) : Constant  Value=40  VectorParams1D=off  OutDataTypeMode=double  OutDataType=sfix(16)  OutScaling=2^0  OutDataTypeStr=double  SampleTime=-1
  Q in{5,20,55,80} (4 alike) : Constant  Value=38  VectorParams1D=off  OutDataTypeMode=double  OutDataType=sfix(16)  OutScaling=2^0  OutDataTypeStr=double  SampleTime=-1
  Q in{6,21,56,81} (4 alike) : Constant  Value=36  VectorParams1D=off  OutDataTypeMode=double  OutDataType=sfix(16)  OutScaling=2^0  OutDataTypeStr=double  SampleTime=-1
  Q in{7,22,57,82} (4 alike) : Constant  Value=34  VectorParams1D=off  OutDataTypeMode=double  OutDataType=sfix(16)  OutScaling=2^0  OutDataTypeStr=double  SampleTime=-1
  Q in{8,23,58,83} (4 alike) : Constant  Value=32  VectorParams1D=off  OutDataTypeMode=double  OutDataType=sfix(16)  OutScaling=2^0  OutDataTypeStr=double  SampleTime=-1
  Q in{9,24,59,84} (4 alike) : Constant  Value=30  VectorParams1D=off  OutDataTypeMode=double  OutDataType=sfix(16)  OutScaling=2^0  OutDataTypeStr=double  SampleTime=-1
  Q in{31,37,67,73} (4 alike) : Constant  Value=16  VectorParams1D=off  OutDataTypeMode=double  OutDataType=sfix(16)  OutScaling=2^0  OutDataTypeStr=double  SampleTime=-1
  Q in{32,38,68,74} (4 alike) : Constant  Value=14  VectorParams1D=off  OutDataTypeMode=double  OutDataType=sfix(16)  OutScaling=2^0  OutDataTypeStr=double  SampleTime=-1
  Q in{33,39,69,75} (4 alike) : Constant  Value=12  VectorParams1D=off  OutDataTypeMode=double  OutDataType=sfix(16)  OutScaling=2^0  OutDataTypeStr=double  SampleTime=-1
  Q in{34,40,70,77} (4 alike) : Constant  Value=10  VectorParams1D=off  OutDataTypeMode=double  OutDataType=sfix(16)  OutScaling=2^0  OutDataTypeStr=double  SampleTime=-1
  Q in{35,41,71,78} (4 alike) : Constant  Value=8  VectorParams1D=off  OutDataTypeMode=double  OutDataType=sfix(16)  OutScaling=2^0  OutDataTypeStr=double  SampleTime=-1
  Q in{36,42,72,79} (4 alike) : Constant  Value=0  VectorParams1D=off  OutDataTypeMode=double  OutDataType=sfix(16)  OutScaling=2^0  OutDataTypeStr=double  SampleTime=-1
  Sum{1..4} (4 alike) : Sum  Inputs=|+++++++++++++++++++++  OutDataType=sfix(16)  OutScaling=2^0
  Switch Case Action1 : Subsystem  TreatAsAtomicUnit=on
  Switch Case Action10 : Subsystem  TreatAsAtomicUnit=on
  Switch Case Action11 : Subsystem  TreatAsAtomicUnit=on
  Switch Case Action12 : Subsystem  TreatAsAtomicUnit=on
  Switch Case Action13 : Subsystem  TreatAsAtomicUnit=on
  Switch Case Action14 : Subsystem  TreatAsAtomicUnit=on
  Switch Case Action15 : Subsystem  TreatAsAtomicUnit=on
  Switch Case Action16 : Subsystem  TreatAsAtomicUnit=on
  Switch Case Action17 : Subsystem  TreatAsAtomicUnit=on
  Switch Case Action18 : Subsystem  TreatAsAtomicUnit=on
  Switch Case Action19 : Subsystem  TreatAsAtomicUnit=on
  Switch Case Action2 : Subsystem  TreatAsAtomicUnit=on
  Switch Case Action20 : Subsystem  TreatAsAtomicUnit=on
  Switch Case Action21 : Subsystem  TreatAsAtomicUnit=on
  Switch Case Action22 : Subsystem  TreatAsAtomicUnit=on
  Switch Case Action23 : Subsystem  TreatAsAtomicUnit=on
  Switch Case Action24 : Subsystem  TreatAsAtomicUnit=on
  Switch Case Action25 : Subsystem  TreatAsAtomicUnit=on
  Switch Case Action26 : Subsystem  TreatAsAtomicUnit=on
  Switch Case Action27 : Subsystem  TreatAsAtomicUnit=on
  Switch Case Action28 : Subsystem  TreatAsAtomicUnit=on
  Switch Case Action29 : Subsystem  TreatAsAtomicUnit=on
  Switch Case Action3 : Subsystem  TreatAsAtomicUnit=on
  Switch Case Action30 : Subsystem  TreatAsAtomicUnit=on
  Switch Case Action31 : Subsystem  TreatAsAtomicUnit=on
  Switch Case Action32 : Subsystem  TreatAsAtomicUnit=on
  Switch Case Action33 : Subsystem  TreatAsAtomicUnit=on
  Switch Case Action34 : Subsystem  TreatAsAtomicUnit=on
  Switch Case Action35 : Subsystem  TreatAsAtomicUnit=on
  Switch Case Action36 : Subsystem  TreatAsAtomicUnit=on
  Switch Case Action37 : Subsystem  TreatAsAtomicUnit=on
  Switch Case Action38 : Subsystem  TreatAsAtomicUnit=on
  Switch Case Action39 : Subsystem  TreatAsAtomicUnit=on
  Switch Case Action4 : Subsystem  TreatAsAtomicUnit=on
  Switch Case Action40 : Subsystem  TreatAsAtomicUnit=on
  Switch Case Action41 : Subsystem  TreatAsAtomicUnit=on
  Switch Case Action42 : Subsystem  TreatAsAtomicUnit=on
  Switch Case Action43 : Subsystem  TreatAsAtomicUnit=on
  Switch Case Action44 : Subsystem  TreatAsAtomicUnit=on
  Switch Case Action45 : Subsystem  TreatAsAtomicUnit=on
  Switch Case Action46 : Subsystem  TreatAsAtomicUnit=on
  Switch Case Action47 : Subsystem  TreatAsAtomicUnit=on
  Switch Case Action48 : Subsystem  TreatAsAtomicUnit=on
  Switch Case Action49 : Subsystem  TreatAsAtomicUnit=on
  Switch Case Action5 : Subsystem  TreatAsAtomicUnit=on
  Switch Case Action50 : Subsystem  TreatAsAtomicUnit=on
  Switch Case Action51 : Subsystem  TreatAsAtomicUnit=on
  Switch Case Action52 : Subsystem  TreatAsAtomicUnit=on
  Switch Case Action53 : Subsystem  TreatAsAtomicUnit=on
  Switch Case Action54 : Subsystem  TreatAsAtomicUnit=on
  Switch Case Action55 : Subsystem  TreatAsAtomicUnit=on
  Switch Case Action56 : Subsystem  TreatAsAtomicUnit=on
  Switch Case Action57 : Subsystem  TreatAsAtomicUnit=on
  Switch Case Action58 : Subsystem  TreatAsAtomicUnit=on
  Switch Case Action59 : Subsystem  TreatAsAtomicUnit=on
  Switch Case Action6 : Subsystem  TreatAsAtomicUnit=on
  Switch Case Action60 : Subsystem  TreatAsAtomicUnit=on
  Switch Case Action61 : Subsystem  TreatAsAtomicUnit=on
  Switch Case Action62 : Subsystem  TreatAsAtomicUnit=on
  Switch Case Action63 : Subsystem  TreatAsAtomicUnit=on
  Switch Case Action64 : Subsystem  TreatAsAtomicUnit=on
  Switch Case Action65 : Subsystem  TreatAsAtomicUnit=on
  Switch Case Action66 : Subsystem  TreatAsAtomicUnit=on
  Switch Case Action67 : Subsystem  TreatAsAtomicUnit=on
  Switch Case Action68 : Subsystem  TreatAsAtomicUnit=on
  Switch Case Action69 : Subsystem  TreatAsAtomicUnit=on
  Switch Case Action7 : Subsystem  TreatAsAtomicUnit=on
  Switch Case Action70 : Subsystem  TreatAsAtomicUnit=on
  Switch Case Action71 : Subsystem  TreatAsAtomicUnit=on
  Switch Case Action72 : Subsystem  TreatAsAtomicUnit=on
  Switch Case Action73 : Subsystem  TreatAsAtomicUnit=on
  Switch Case Action74 : Subsystem  TreatAsAtomicUnit=on
  Switch Case Action75 : Subsystem  TreatAsAtomicUnit=on
  Switch Case Action76 : Subsystem  TreatAsAtomicUnit=on
  Switch Case Action77 : Subsystem  TreatAsAtomicUnit=on
  Switch Case Action78 : Subsystem  TreatAsAtomicUnit=on
  Switch Case Action79 : Subsystem  TreatAsAtomicUnit=on
  Switch Case Action8 : Subsystem  TreatAsAtomicUnit=on
  Switch Case Action80 : Subsystem  TreatAsAtomicUnit=on
  Switch Case Action81 : Subsystem  TreatAsAtomicUnit=on
  Switch Case Action82 : Subsystem  TreatAsAtomicUnit=on
  Switch Case Action83 : Subsystem  TreatAsAtomicUnit=on
  Switch Case Action84 : Subsystem  TreatAsAtomicUnit=on
  Switch Case Action9 : Subsystem  TreatAsAtomicUnit=on
  Out1 : Outport  OutDataType=sfix(16)  OutScaling=2^0
  Out2 : Outport  Port=2  OutDataType=sfix(16)  OutScaling=2^0
  Out3 : Outport  Port=3  OutDataType=sfix(16)  OutScaling=2^0
  Out4 : Outport  Port=4  OutDataType=sfix(16)  OutScaling=2^0
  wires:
  Klasifikacia2/1 -> Switch Case Action17/Action
  Klasifikacia2/2 -> Switch Case Action18/Action
  Klasifikacia2/3 -> Switch Case Action19/Action
  Klasifikacia2/4 -> Switch Case Action20/Action
  Switch Case Action17/1(Out1) -> Sum3/1
  Switch Case Action18/1(Out1) -> Sum3/2
  Switch Case Action19/1(Out1) -> Sum3/3
  Switch Case Action20/1(Out1) -> Sum3/4
  Q in16/1 -> Switch Case Action17/1(In1)
  Q in17/1 -> Switch Case Action18/1(In1)
  Q in18/1 -> Switch Case Action19/1(In1)
  Q in19/1 -> Switch Case Action20/1(In1)
  Q in20/1 -> Switch Case Action21/1(In1)
  Q in21/1 -> Switch Case Action22/1(In1)
  Q in22/1 -> Switch Case Action23/1(In1)
  Q in23/1 -> Switch Case Action24/1(In1)
  Q in24/1 -> Switch Case Action25/1(In1)
  Q in25/1 -> Switch Case Action26/1(In1)
  Q in26/1 -> Switch Case Action27/1(In1)
  Q in27/1 -> Switch Case Action28/1(In1)
  Q in28/1 -> Switch Case Action29/1(In1)
  Q in29/1 -> Switch Case Action30/1(In1)
  Q in30/1 -> Switch Case Action31/1(In1)
  Q in31/1 -> Switch Case Action32/1(In1)
  Q in32/1 -> Switch Case Action33/1(In1)
  Q in33/1 -> Switch Case Action34/1(In1)
  Q in34/1 -> Switch Case Action35/1(In1)
  Q in35/1 -> Switch Case Action36/1(In1)
  Q in36/1 -> Switch Case Action37/1(In1)
  Klasifikacia2/5 -> Switch Case Action21/Action
  Klasifikacia2/6 -> Switch Case Action22/Action
  Klasifikacia2/7 -> Switch Case Action23/Action
  Klasifikacia2/8 -> Switch Case Action24/Action
  Klasifikacia2/9 -> Switch Case Action25/Action
  Klasifikacia2/10 -> Switch Case Action26/Action
  Klasifikacia2/11 -> Switch Case Action27/Action
  Klasifikacia2/12 -> Switch Case Action28/Action
  Klasifikacia2/13 -> Switch Case Action29/Action
  Klasifikacia2/14 -> Switch Case Action30/Action
  Klasifikacia2/15 -> Switch Case Action31/Action
  Klasifikacia2/16 -> Switch Case Action32/Action
  Klasifikacia2/17 -> Switch Case Action33/Action
  Klasifikacia2/18 -> Switch Case Action34/Action
  Klasifikacia2/19 -> Switch Case Action35/Action
  Klasifikacia2/20 -> Switch Case Action36/Action
  Klasifikacia2/21 -> Switch Case Action37/Action
  Switch Case Action21/1(Out1) -> Sum3/5
  Switch Case Action22/1(Out1) -> Sum3/6
  Switch Case Action23/1(Out1) -> Sum3/7
  Switch Case Action24/1(Out1) -> Sum3/8
  Switch Case Action37/1(Out1) -> Sum3/21
  Switch Case Action36/1(Out1) -> Sum3/20
  Switch Case Action35/1(Out1) -> Sum3/19
  Switch Case Action34/1(Out1) -> Sum3/18
  Switch Case Action33/1(Out1) -> Sum3/17
  Switch Case Action32/1(Out1) -> Sum3/16
  Switch Case Action31/1(Out1) -> Sum3/15
  Switch Case Action30/1(Out1) -> Sum3/14
  Switch Case Action29/1(Out1) -> Sum3/13
  Switch Case Action28/1(Out1) -> Sum3/12
  Switch Case Action27/1(Out1) -> Sum3/11
  Switch Case Action26/1(Out1) -> Sum3/10
  Switch Case Action25/1(Out1) -> Sum3/9
  Mux1/1 -> "     1"/1(x)
  "     1"/1(y) -> Demux1/1
  Demux1/1 -> Out1/1
  Demux1/2 -> Out2/1
  Demux1/3 -> Out3/1
  Demux1/4 -> Out4/1
  Klasifikacia1/1 -> Switch Case Action1/Action
  Klasifikacia1/2 -> Switch Case Action2/Action
  Klasifikacia1/3 -> Switch Case Action3/Action
  Klasifikacia1/4 -> Switch Case Action4/Action
  Switch Case Action1/1(Out1) -> Sum1/1
  Switch Case Action2/1(Out1) -> Sum1/2
  Switch Case Action3/1(Out1) -> Sum1/3
  Switch Case Action4/1(Out1) -> Sum1/4
  Q in1/1 -> Switch Case Action1/1(In1)
  Q in2/1 -> Switch Case Action2/1(In1)
  Q in3/1 -> Switch Case Action3/1(In1)
  Q in4/1 -> Switch Case Action4/1(In1)
  Q in5/1 -> Switch Case Action5/1(In1)
  Q in6/1 -> Switch Case Action6/1(In1)
  Q in7/1 -> Switch Case Action7/1(In1)
  Q in8/1 -> Switch Case Action8/1(In1)
  Q in9/1 -> Switch Case Action9/1(In1)
  Q in10/1 -> Switch Case Action10/1(In1)
  Q in11/1 -> Switch Case Action11/1(In1)
  Q in12/1 -> Switch Case Action12/1(In1)
  Q in13/1 -> Switch Case Action13/1(In1)
  Q in14/1 -> Switch Case Action14/1(In1)
  Q in15/1 -> Switch Case Action15/1(In1)
  Q in37/1 -> Switch Case Action16/1(In1)
  Q in38/1 -> Switch Case Action38/1(In1)
  Q in39/1 -> Switch Case Action39/1(In1)
  Q in40/1 -> Switch Case Action40/1(In1)
  Q in41/1 -> Switch Case Action41/1(In1)
  Q in42/1 -> Switch Case Action42/1(In1)
  Klasifikacia1/5 -> Switch Case Action5/Action
  Klasifikacia1/6 -> Switch Case Action6/Action
  Klasifikacia1/7 -> Switch Case Action7/Action
  Klasifikacia1/8 -> Switch Case Action8/Action
  Klasifikacia1/9 -> Switch Case Action9/Action
  Klasifikacia1/10 -> Switch Case Action10/Action
  Klasifikacia1/11 -> Switch Case Action11/Action
  Klasifikacia1/12 -> Switch Case Action12/Action
  Klasifikacia1/13 -> Switch Case Action13/Action
  Klasifikacia1/14 -> Switch Case Action14/Action
  Klasifikacia1/15 -> Switch Case Action15/Action
  Klasifikacia1/16 -> Switch Case Action16/Action
  Klasifikacia1/17 -> Switch Case Action38/Action
  Klasifikacia1/18 -> Switch Case Action39/Action
  Klasifikacia1/19 -> Switch Case Action40/Action
  Klasifikacia1/20 -> Switch Case Action41/Action
  Klasifikacia1/21 -> Switch Case Action42/Action
  Switch Case Action5/1(Out1) -> Sum1/5
  Switch Case Action6/1(Out1) -> Sum1/6
  Switch Case Action7/1(Out1) -> Sum1/7
  Switch Case Action8/1(Out1) -> Sum1/8
  Switch Case Action42/1(Out1) -> Sum1/21
  Switch Case Action41/1(Out1) -> Sum1/20
  Switch Case Action40/1(Out1) -> Sum1/19
  Switch Case Action39/1(Out1) -> Sum1/18
  Switch Case Action38/1(Out1) -> Sum1/17
  Switch Case Action16/1(Out1) -> Sum1/16
  Switch Case Action15/1(Out1) -> Sum1/15
  Switch Case Action14/1(Out1) -> Sum1/14
  Switch Case Action13/1(Out1) -> Sum1/13
  Switch Case Action12/1(Out1) -> Sum1/12
  Switch Case Action11/1(Out1) -> Sum1/11
  Switch Case Action10/1(Out1) -> Sum1/10
  Switch Case Action9/1(Out1) -> Sum1/9
  In3/1 -> Klasifikacia4/1
  Klasifikacia4/1 -> Switch Case Action51/Action
  Klasifikacia4/2 -> Switch Case Action52/Action
  Klasifikacia4/3 -> Switch Case Action53/Action
  Klasifikacia4/4 -> Switch Case Action55/Action
  Switch Case Action51/1(Out1) -> Sum4/1
  Switch Case Action52/1(Out1) -> Sum4/2
  Switch Case Action53/1(Out1) -> Sum4/3
  Switch Case Action55/1(Out1) -> Sum4/4
  Q in50/1 -> Switch Case Action51/1(In1)
  Q in51/1 -> Switch Case Action52/1(In1)
  Q in52/1 -> Switch Case Action53/1(In1)
  Q in53/1 -> Switch Case Action55/1(In1)
  Q in55/1 -> Switch Case Action56/1(In1)
  Q in56/1 -> Switch Case Action57/1(In1)
  Q in57/1 -> Switch Case Action58/1(In1)
  Q in58/1 -> Switch Case Action59/1(In1)
  Q in59/1 -> Switch Case Action60/1(In1)
  Q in60/1 -> Switch Case Action61/1(In1)
  Q in61/1 -> Switch Case Action62/1(In1)
  Q in62/1 -> Switch Case Action63/1(In1)
  Q in63/1 -> Switch Case Action64/1(In1)
  Q in64/1 -> Switch Case Action66/1(In1)
  Q in66/1 -> Switch Case Action67/1(In1)
  Q in67/1 -> Switch Case Action68/1(In1)
  Q in68/1 -> Switch Case Action69/1(In1)
  Q in69/1 -> Switch Case Action70/1(In1)
  Q in70/1 -> Switch Case Action71/1(In1)
  Q in71/1 -> Switch Case Action72/1(In1)
  Q in72/1 -> Switch Case Action73/1(In1)
  Klasifikacia4/5 -> Switch Case Action56/Action
  Klasifikacia4/6 -> Switch Case Action57/Action
  Klasifikacia4/7 -> Switch Case Action58/Action
  Klasifikacia4/8 -> Switch Case Action59/Action
  Klasifikacia4/9 -> Switch Case Action60/Action
  Klasifikacia4/10 -> Switch Case Action61/Action
  Klasifikacia4/11 -> Switch Case Action62/Action
  Klasifikacia4/12 -> Switch Case Action63/Action
  Klasifikacia4/13 -> Switch Case Action64/Action
  Klasifikacia4/14 -> Switch Case Action66/Action
  Klasifikacia4/15 -> Switch Case Action67/Action
  Klasifikacia4/16 -> Switch Case Action68/Action
  Klasifikacia4/17 -> Switch Case Action69/Action
  Klasifikacia4/18 -> Switch Case Action70/Action
  Klasifikacia4/19 -> Switch Case Action71/Action
  Klasifikacia4/20 -> Switch Case Action72/Action
  Klasifikacia4/21 -> Switch Case Action73/Action
  Switch Case Action56/1(Out1) -> Sum4/5
  Switch Case Action57/1(Out1) -> Sum4/6
  Switch Case Action58/1(Out1) -> Sum4/7
  Switch Case Action59/1(Out1) -> Sum4/8
  Switch Case Action73/1(Out1) -> Sum4/21
  Switch Case Action72/1(Out1) -> Sum4/20
  Switch Case Action71/1(Out1) -> Sum4/19
  Switch Case Action70/1(Out1) -> Sum4/18
  Switch Case Action69/1(Out1) -> Sum4/17
  Switch Case Action68/1(Out1) -> Sum4/16
  Switch Case Action67/1(Out1) -> Sum4/15
  Switch Case Action66/1(Out1) -> Sum4/14
  Switch Case Action64/1(Out1) -> Sum4/13
  Switch Case Action63/1(Out1) -> Sum4/12
  Switch Case Action62/1(Out1) -> Sum4/11
  Switch Case Action61/1(Out1) -> Sum4/10
  Switch Case Action60/1(Out1) -> Sum4/9
  In4/1 -> Klasifikacia3/1
  Klasifikacia3/1 -> Switch Case Action43/Action
  Klasifikacia3/2 -> Switch Case Action54/Action
  Klasifikacia3/3 -> Switch Case Action65/Action
  Klasifikacia3/4 -> Switch Case Action76/Action
  Switch Case Action43/1(Out1) -> Sum2/1
  Switch Case Action54/1(Out1) -> Sum2/2
  Switch Case Action65/1(Out1) -> Sum2/3
  Switch Case Action76/1(Out1) -> Sum2/4
  Q in43/1 -> Switch Case Action43/1(In1)
  Q in54/1 -> Switch Case Action54/1(In1)
  Q in65/1 -> Switch Case Action65/1(In1)
  Q in76/1 -> Switch Case Action76/1(In1)
  Q in80/1 -> Switch Case Action80/1(In1)
  Q in81/1 -> Switch Case Action81/1(In1)
  Q in82/1 -> Switch Case Action82/1(In1)
  Q in83/1 -> Switch Case Action83/1(In1)
  Q in84/1 -> Switch Case Action84/1(In1)
  Q in44/1 -> Switch Case Action44/1(In1)
  Q in45/1 -> Switch Case Action45/1(In1)
  Q in46/1 -> Switch Case Action46/1(In1)
  Q in47/1 -> Switch Case Action47/1(In1)
  Q in48/1 -> Switch Case Action48/1(In1)
  Q in49/1 -> Switch Case Action49/1(In1)
  Q in73/1 -> Switch Case Action50/1(In1)
  Q in74/1 -> Switch Case Action74/1(In1)
  Q in75/1 -> Switch Case Action75/1(In1)
  Q in77/1 -> Switch Case Action77/1(In1)
  Q in78/1 -> Switch Case Action78/1(In1)
  Q in79/1 -> Switch Case Action79/1(In1)
  Klasifikacia3/5 -> Switch Case Action80/Action
  Klasifikacia3/6 -> Switch Case Action81/Action
  Klasifikacia3/7 -> Switch Case Action82/Action
  Klasifikacia3/8 -> Switch Case Action83/Action
  Klasifikacia3/9 -> Switch Case Action84/Action
  Klasifikacia3/10 -> Switch Case Action44/Action
  Klasifikacia3/11 -> Switch Case Action45/Action
  Klasifikacia3/12 -> Switch Case Action46/Action
  Klasifikacia3/13 -> Switch Case Action47/Action
  Klasifikacia3/14 -> Switch Case Action48/Action
  Klasifikacia3/15 -> Switch Case Action49/Action
  Klasifikacia3/16 -> Switch Case Action50/Action
  Klasifikacia3/17 -> Switch Case Action74/Action
  Klasifikacia3/18 -> Switch Case Action75/Action
  Klasifikacia3/19 -> Switch Case Action77/Action
  Klasifikacia3/20 -> Switch Case Action78/Action
  Klasifikacia3/21 -> Switch Case Action79/Action
  Switch Case Action80/1(Out1) -> Sum2/5
  Switch Case Action81/1(Out1) -> Sum2/6
  Switch Case Action82/1(Out1) -> Sum2/7
  Switch Case Action83/1(Out1) -> Sum2/8
  Switch Case Action79/1(Out1) -> Sum2/21
  Switch Case Action78/1(Out1) -> Sum2/20
  Switch Case Action77/1(Out1) -> Sum2/19
  Switch Case Action75/1(Out1) -> Sum2/18
  Switch Case Action74/1(Out1) -> Sum2/17
  Switch Case Action50/1(Out1) -> Sum2/16
  Switch Case Action49/1(Out1) -> Sum2/15
  Switch Case Action48/1(Out1) -> Sum2/14
  Switch Case Action47/1(Out1) -> Sum2/13
  Switch Case Action46/1(Out1) -> Sum2/12
  Switch Case Action45/1(Out1) -> Sum2/11
  Switch Case Action44/1(Out1) -> Sum2/10
  Switch Case Action84/1(Out1) -> Sum2/9
  Sum4/1 -> Mux1/1
  Sum2/1 -> Mux1/2
  Sum3/1 -> Mux1/3
  Sum1/1 -> Mux1/4
  In1/1 -> Klasifikacia2/1
  In2/1 -> Klasifikacia1/1

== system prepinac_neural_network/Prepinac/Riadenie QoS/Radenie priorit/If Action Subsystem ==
  In1 : Inport  OutDataType=sfix(16)  OutScaling=2^0
  Action Port : ActionPort  ActionType=then
  Out1 : Outport  OutDataType=sfix(16)  OutScaling=2^0
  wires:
  In1/1 -> Out1/1

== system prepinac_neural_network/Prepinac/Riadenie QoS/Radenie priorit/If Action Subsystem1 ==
  In1 : Inport  OutDataType=sfix(16)  OutScaling=2^0
  Action Port : ActionPort  ActionType=elseif
  Out1 : Outport  OutDataType=sfix(16)  OutScaling=2^0
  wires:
  In1/1 -> Out1/1

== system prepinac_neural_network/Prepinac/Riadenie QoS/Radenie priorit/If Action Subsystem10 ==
  In1 : Inport  OutDataType=sfix(16)  OutScaling=2^0
  Action Port : ActionPort  ActionType=then
  Out1 : Outport  OutDataType=sfix(16)  OutScaling=2^0
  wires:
  In1/1 -> Out1/1

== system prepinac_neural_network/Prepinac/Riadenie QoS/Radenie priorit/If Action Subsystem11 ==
  In1 : Inport  OutDataType=sfix(16)  OutScaling=2^0
  Action Port : ActionPort  ActionType=elseif
  Out1 : Outport  OutDataType=sfix(16)  OutScaling=2^0
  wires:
  In1/1 -> Out1/1

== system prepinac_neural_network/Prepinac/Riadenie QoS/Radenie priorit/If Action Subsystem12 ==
  In1 : Inport  OutDataType=sfix(16)  OutScaling=2^0
  Action Port : ActionPort  ActionType=then
  Out1 : Outport  OutDataType=sfix(16)  OutScaling=2^0
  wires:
  In1/1 -> Out1/1

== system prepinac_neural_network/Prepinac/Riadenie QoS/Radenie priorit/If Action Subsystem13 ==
  In1 : Inport  OutDataType=sfix(16)  OutScaling=2^0
  Action Port : ActionPort  ActionType=elseif
  Out1 : Outport  OutDataType=sfix(16)  OutScaling=2^0
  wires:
  In1/1 -> Out1/1

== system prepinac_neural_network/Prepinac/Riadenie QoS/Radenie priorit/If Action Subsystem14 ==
  In1 : Inport  OutDataType=sfix(16)  OutScaling=2^0
  Action Port : ActionPort  ActionType=then
  Out1 : Outport  OutDataType=sfix(16)  OutScaling=2^0
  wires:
  In1/1 -> Out1/1

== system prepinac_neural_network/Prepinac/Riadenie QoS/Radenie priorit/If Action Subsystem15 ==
  In1 : Inport  OutDataType=sfix(16)  OutScaling=2^0
  Action Port : ActionPort  ActionType=elseif
  Out1 : Outport  OutDataType=sfix(16)  OutScaling=2^0
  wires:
  In1/1 -> Out1/1

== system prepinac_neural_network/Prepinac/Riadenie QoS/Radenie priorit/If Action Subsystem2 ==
  In1 : Inport  OutDataType=sfix(16)  OutScaling=2^0
  Action Port : ActionPort  ActionType=then
  Out1 : Outport  OutDataType=sfix(16)  OutScaling=2^0
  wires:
  In1/1 -> Out1/1

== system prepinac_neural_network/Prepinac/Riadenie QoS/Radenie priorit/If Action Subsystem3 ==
  In1 : Inport  OutDataType=sfix(16)  OutScaling=2^0
  Action Port : ActionPort  ActionType=elseif
  Out1 : Outport  OutDataType=sfix(16)  OutScaling=2^0
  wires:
  In1/1 -> Out1/1

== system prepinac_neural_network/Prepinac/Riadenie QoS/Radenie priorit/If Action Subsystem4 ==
  In1 : Inport  OutDataType=sfix(16)  OutScaling=2^0
  Action Port : ActionPort  ActionType=then
  Out1 : Outport  OutDataType=sfix(16)  OutScaling=2^0
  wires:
  In1/1 -> Out1/1

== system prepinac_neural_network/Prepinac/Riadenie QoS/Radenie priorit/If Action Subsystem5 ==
  In1 : Inport  OutDataType=sfix(16)  OutScaling=2^0
  Action Port : ActionPort  ActionType=elseif
  Out1 : Outport  OutDataType=sfix(16)  OutScaling=2^0
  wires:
  In1/1 -> Out1/1

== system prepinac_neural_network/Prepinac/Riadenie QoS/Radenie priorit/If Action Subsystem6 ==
  In1 : Inport  OutDataType=sfix(16)  OutScaling=2^0
  Action Port : ActionPort  ActionType=then
  Out1 : Outport  OutDataType=sfix(16)  OutScaling=2^0
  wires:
  In1/1 -> Out1/1

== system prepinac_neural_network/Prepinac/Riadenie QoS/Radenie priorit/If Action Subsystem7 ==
  In1 : Inport  OutDataType=sfix(16)  OutScaling=2^0
  Action Port : ActionPort  ActionType=elseif
  Out1 : Outport  OutDataType=sfix(16)  OutScaling=2^0
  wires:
  In1/1 -> Out1/1

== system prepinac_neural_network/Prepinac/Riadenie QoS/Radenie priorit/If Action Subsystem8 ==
  In1 : Inport  OutDataType=sfix(16)  OutScaling=2^0
  Action Port : ActionPort  ActionType=then
  Out1 : Outport  OutDataType=sfix(16)  OutScaling=2^0
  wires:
  In1/1 -> Out1/1

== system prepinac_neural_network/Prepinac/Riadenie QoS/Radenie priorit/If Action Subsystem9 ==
  In1 : Inport  OutDataType=sfix(16)  OutScaling=2^0
  Action Port : ActionPort  ActionType=elseif
  Out1 : Outport  OutDataType=sfix(16)  OutScaling=2^0
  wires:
  In1/1 -> Out1/1

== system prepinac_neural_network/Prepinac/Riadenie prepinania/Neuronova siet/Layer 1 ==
  "p{1}" : Inport  PortDimensions=8  SampleTime=1  OutDataType=sfix(16)  OutScaling=2^0
  Delays 1 : Subsystem
  "IW{1,1}" : Subsystem
  "b{1}" : Constant  Value=[0.58614867089452694;-5.1017435870068804;-1.6845353841598583;4.236951486817234;-3.7865577732911646;-3.8421470684760379;2.0014106473615447;1.933915855851819;-0.34768318253365205;-2.4665376933003365;-2.641937093429318;0.10540146849758207;-0.27924093955458612;-2.0889268744022207;1.1949435393710357;0.40784066091331905;-1.1469079646074991;1.3609136971806051;-2.6300009390013011;0.63920739825583472]  OutDataType=sfix(16)  OutScaling=2^0
  netsum : Sum  Inputs=2  OutDataType=sfix(16)  OutScaling=2^0
  tansig : neural/Transfer Functions/tansig  SystemSampleTime=-1
  "a{1}" : Outport  OutDataType=sfix(16)  OutScaling=2^0  InitialOutput=[0;0;0;0;0;0;0;0;0;0;0;0;0;0;0;0;0;0;0;0]
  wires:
  "p{1}"/1 -> Delays 1/1("p{1}")
  Delays 1/1("pd{1,1}") -> "IW{1,1}"/1("pd{1,1}")
  "IW{1,1}"/1("iz{1,1}") -> netsum/1
  "b{1}"/1 -> netsum/2
  netsum/1 -> tansig/1
  tansig/1 -> "a{1}"/1

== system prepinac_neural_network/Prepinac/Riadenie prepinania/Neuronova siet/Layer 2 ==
  "a{1} " : Inport  PortDimensions=20  SampleTime=1  OutDataType=sfix(16)  OutScaling=2^0
  Delays 1 : Subsystem
  "LW{2,1}" : Subsystem
  "b{2}" : Constant  Value=[0.29749609877982408;0.099807172382475495;-0.26626110234529693;0.70577592335529615]  OutDataType=sfix(16)  OutScaling=2^0
  netsum : Sum  Inputs=2  OutDataType=sfix(16)  OutScaling=2^0
  tansig : neural/Transfer Functions/tansig  SystemSampleTime=-1
  "a{2}" : Outport  OutDataType=sfix(16)  OutScaling=2^0  InitialOutput=[0;0;0;0;0;0;0;0]
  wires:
  "a{1} "/1 -> Delays 1/1("p{2}")
  Delays 1/1("pd{2,1}") -> "LW{2,1}"/1("ad{2,1}")
  "LW{2,1}"/1("lz{2,1}") -> netsum/1
  "b{2}"/1 -> netsum/2
  netsum/1 -> tansig/1
  tansig/1 -> "a{2}"/1

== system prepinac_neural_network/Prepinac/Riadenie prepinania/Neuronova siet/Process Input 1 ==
  x : Inport  PortDimensions=1  SampleTime=1
  p : Outport  PortDimensions=1  SampleTime=1
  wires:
  x/1 -> p/1

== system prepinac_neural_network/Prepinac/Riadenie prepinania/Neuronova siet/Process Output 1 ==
  a : Inport  PortDimensions=1  SampleTime=1
  y : Outport  PortDimensions=1  SampleTime=1
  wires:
  a/1 -> y/1

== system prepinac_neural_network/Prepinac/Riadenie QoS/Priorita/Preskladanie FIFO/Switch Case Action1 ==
  In1 : Inport  OutDataType=sfix(16)  OutScaling=2^0
  Action Port : ActionPort
  Out1 : Outport  OutDataType=sfix(16)  OutScaling=2^0
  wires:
  In1/1 -> Out1/1

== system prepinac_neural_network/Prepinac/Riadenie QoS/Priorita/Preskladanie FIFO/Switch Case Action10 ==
  In1 : Inport  OutDataType=sfix(16)  OutScaling=2^0
  Action Port : ActionPort
  Out1 : Outport  OutDataType=sfix(16)  OutScaling=2^0
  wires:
  In1/1 -> Out1/1

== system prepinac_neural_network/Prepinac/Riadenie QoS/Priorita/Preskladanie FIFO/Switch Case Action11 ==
  In1 : Inport  OutDataType=sfix(16)  OutScaling=2^0
  Action Port : ActionPort
  Out1 : Outport  OutDataType=sfix(16)  OutScaling=2^0
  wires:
  In1/1 -> Out1/1

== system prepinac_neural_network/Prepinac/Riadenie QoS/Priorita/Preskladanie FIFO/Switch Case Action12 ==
  In1 : Inport  OutDataType=sfix(16)  OutScaling=2^0
  Action Port : ActionPort
  Out1 : Outport  OutDataType=sfix(16)  OutScaling=2^0
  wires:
  In1/1 -> Out1/1

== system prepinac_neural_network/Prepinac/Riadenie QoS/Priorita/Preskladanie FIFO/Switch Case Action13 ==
  In1 : Inport  OutDataType=sfix(16)  OutScaling=2^0
  Action Port : ActionPort
  Out1 : Outport  OutDataType=sfix(16)  OutScaling=2^0
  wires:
  In1/1 -> Out1/1

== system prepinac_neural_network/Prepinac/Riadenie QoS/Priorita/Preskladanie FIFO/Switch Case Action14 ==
  In1 : Inport  OutDataType=sfix(16)  OutScaling=2^0
  Action Port : ActionPort
  Out1 : Outport  OutDataType=sfix(16)  OutScaling=2^0
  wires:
  In1/1 -> Out1/1

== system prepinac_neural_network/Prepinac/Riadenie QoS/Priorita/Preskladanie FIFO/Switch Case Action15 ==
  In1 : Inport  OutDataType=sfix(16)  OutScaling=2^0
  Action Port : ActionPort
  Out1 : Outport  OutDataType=sfix(16)  OutScaling=2^0
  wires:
  In1/1 -> Out1/1

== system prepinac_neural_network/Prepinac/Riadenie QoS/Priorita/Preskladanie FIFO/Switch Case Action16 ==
  In1 : Inport  OutDataType=sfix(16)  OutScaling=2^0
  Action Port : ActionPort
  Out1 : Outport  OutDataType=sfix(16)  OutScaling=2^0
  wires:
  In1/1 -> Out1/1

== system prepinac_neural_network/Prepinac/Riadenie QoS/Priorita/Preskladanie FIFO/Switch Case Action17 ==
  In1 : Inport  OutDataType=sfix(16)  OutScaling=2^0
  Action Port : ActionPort
  Out1 : Outport  OutDataType=sfix(16)  OutScaling=2^0
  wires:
  In1/1 -> Out1/1

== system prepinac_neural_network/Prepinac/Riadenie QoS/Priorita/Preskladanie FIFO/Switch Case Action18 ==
  In1 : Inport  OutDataType=sfix(16)  OutScaling=2^0
  Action Port : ActionPort
  Out1 : Outport  OutDataType=sfix(16)  OutScaling=2^0
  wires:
  In1/1 -> Out1/1

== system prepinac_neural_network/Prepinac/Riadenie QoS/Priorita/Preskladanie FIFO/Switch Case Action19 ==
  In1 : Inport  OutDataType=sfix(16)  OutScaling=2^0
  Action Port : ActionPort
  Out1 : Outport  OutDataType=sfix(16)  OutScaling=2^0
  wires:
  In1/1 -> Out1/1

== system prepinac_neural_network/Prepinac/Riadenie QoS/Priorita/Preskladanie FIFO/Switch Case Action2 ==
  In1 : Inport  OutDataType=sfix(16)  OutScaling=2^0
  Action Port : ActionPort
  Out1 : Outport  OutDataType=sfix(16)  OutScaling=2^0
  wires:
  In1/1 -> Out1/1

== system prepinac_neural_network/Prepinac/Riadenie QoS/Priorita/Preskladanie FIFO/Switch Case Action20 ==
  In1 : Inport  OutDataType=sfix(16)  OutScaling=2^0
  Action Port : ActionPort
  Out1 : Outport  OutDataType=sfix(16)  OutScaling=2^0
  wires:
  In1/1 -> Out1/1

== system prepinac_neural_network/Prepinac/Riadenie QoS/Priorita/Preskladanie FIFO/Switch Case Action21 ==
  In1 : Inport  OutDataType=sfix(16)  OutScaling=2^0
  Action Port : ActionPort
  Out1 : Outport  OutDataType=sfix(16)  OutScaling=2^0
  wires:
  In1/1 -> Out1/1

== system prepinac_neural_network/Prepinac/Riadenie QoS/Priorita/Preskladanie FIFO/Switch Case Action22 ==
  In1 : Inport  OutDataType=sfix(16)  OutScaling=2^0
  Action Port : ActionPort
  Out1 : Outport  OutDataType=sfix(16)  OutScaling=2^0
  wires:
  In1/1 -> Out1/1

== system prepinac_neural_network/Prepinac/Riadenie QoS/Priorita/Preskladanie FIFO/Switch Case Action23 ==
  In1 : Inport  OutDataType=sfix(16)  OutScaling=2^0
  Action Port : ActionPort
  Out1 : Outport  OutDataType=sfix(16)  OutScaling=2^0
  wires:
  In1/1 -> Out1/1

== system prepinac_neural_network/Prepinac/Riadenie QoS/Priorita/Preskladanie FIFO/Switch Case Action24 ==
  In1 : Inport  OutDataType=sfix(16)  OutScaling=2^0
  Action Port : ActionPort
  Out1 : Outport  OutDataType=sfix(16)  OutScaling=2^0
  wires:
  In1/1 -> Out1/1

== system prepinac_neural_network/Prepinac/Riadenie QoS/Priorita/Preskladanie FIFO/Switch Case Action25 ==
  In1 : Inport  OutDataType=sfix(16)  OutScaling=2^0
  Action Port : ActionPort
  Out1 : Outport  OutDataType=sfix(16)  OutScaling=2^0
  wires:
  In1/1 -> Out1/1

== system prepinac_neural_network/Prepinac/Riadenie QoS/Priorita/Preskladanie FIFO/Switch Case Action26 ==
  In1 : Inport  OutDataType=sfix(16)  OutScaling=2^0
  Action Port : ActionPort
  Out1 : Outport  OutDataType=sfix(16)  OutScaling=2^0
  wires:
  In1/1 -> Out1/1

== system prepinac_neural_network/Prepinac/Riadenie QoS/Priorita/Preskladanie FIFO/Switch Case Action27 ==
  In1 : Inport  OutDataType=sfix(16)  OutScaling=2^0
  Action Port : ActionPort
  Out1 : Outport  OutDataType=sfix(16)  OutScaling=2^0
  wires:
  In1/1 -> Out1/1

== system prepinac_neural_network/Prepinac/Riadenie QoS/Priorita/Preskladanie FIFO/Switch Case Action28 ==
  In1 : Inport  OutDataType=sfix(16)  OutScaling=2^0
  Action Port : ActionPort
  Out1 : Outport  OutDataType=sfix(16)  OutScaling=2^0
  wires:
  In1/1 -> Out1/1

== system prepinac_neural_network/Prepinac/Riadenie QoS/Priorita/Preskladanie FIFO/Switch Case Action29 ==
  In1 : Inport  OutDataType=sfix(16)  OutScaling=2^0
  Action Port : ActionPort
  Out1 : Outport  OutDataType=sfix(16)  OutScaling=2^0
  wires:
  In1/1 -> Out1/1

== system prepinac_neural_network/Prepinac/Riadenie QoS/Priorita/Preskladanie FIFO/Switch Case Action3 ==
  In1 : Inport  OutDataType=sfix(16)  OutScaling=2^0
  Action Port : ActionPort
  Out1 : Outport  OutDataType=sfix(16)  OutScaling=2^0
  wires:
  In1/1 -> Out1/1

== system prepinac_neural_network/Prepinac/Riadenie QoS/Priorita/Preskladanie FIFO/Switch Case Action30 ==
  In1 : Inport  OutDataType=sfix(16)  OutScaling=2^0
  Action Port : ActionPort
  Out1 : Outport  OutDataType=sfix(16)  OutScaling=2^0
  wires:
  In1/1 -> Out1/1

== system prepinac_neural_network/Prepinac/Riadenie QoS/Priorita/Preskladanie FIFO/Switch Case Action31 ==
  In1 : Inport  OutDataType=sfix(16)  OutScaling=2^0
  Action Port : ActionPort
  Out1 : Outport  OutDataType=sfix(16)  OutScaling=2^0
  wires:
  In1/1 -> Out1/1

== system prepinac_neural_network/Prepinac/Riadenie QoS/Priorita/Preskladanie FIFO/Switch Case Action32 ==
  In1 : Inport  OutDataType=sfix(16)  OutScaling=2^0
  Action Port : ActionPort
  Out1 : Outport  OutDataType=sfix(16)  OutScaling=2^0
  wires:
  In1/1 -> Out1/1

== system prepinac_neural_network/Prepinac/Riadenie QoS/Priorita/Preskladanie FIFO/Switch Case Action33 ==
  In1 : Inport  OutDataType=sfix(16)  OutScaling=2^0
  Action Port : ActionPort
  Out1 : Outport  OutDataType=sfix(16)  OutScaling=2^0
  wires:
  In1/1 -> Out1/1

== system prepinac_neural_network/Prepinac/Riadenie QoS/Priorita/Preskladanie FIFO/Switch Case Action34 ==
  In1 : Inport  OutDataType=sfix(16)  OutScaling=2^0
  Action Port : ActionPort
  Out1 : Outport  OutDataType=sfix(16)  OutScaling=2^0
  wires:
  In1/1 -> Out1/1

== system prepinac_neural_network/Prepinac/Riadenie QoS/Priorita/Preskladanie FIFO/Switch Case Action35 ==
  In1 : Inport  OutDataType=sfix(16)  OutScaling=2^0
  Action Port : ActionPort
  Out1 : Outport  OutDataType=sfix(16)  OutScaling=2^0
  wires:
  In1/1 -> Out1/1

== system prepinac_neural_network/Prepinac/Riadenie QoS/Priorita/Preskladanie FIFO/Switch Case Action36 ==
  In1 : Inport  OutDataType=sfix(16)  OutScaling=2^0
  Action Port : ActionPort
  Out1 : Outport  OutDataType=sfix(16)  OutScaling=2^0
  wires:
  In1/1 -> Out1/1

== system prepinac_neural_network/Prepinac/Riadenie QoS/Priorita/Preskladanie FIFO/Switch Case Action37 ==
  In1 : Inport  OutDataType=sfix(16)  OutScaling=2^0
  Action Port : ActionPort
  Out1 : Outport  OutDataType=sfix(16)  OutScaling=2^0
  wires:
  In1/1 -> Out1/1

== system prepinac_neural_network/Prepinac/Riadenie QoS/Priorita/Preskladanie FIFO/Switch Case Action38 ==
  In1 : Inport  OutDataType=sfix(16)  OutScaling=2^0
  Action Port : ActionPort
  Out1 : Outport  OutDataType=sfix(16)  OutScaling=2^0
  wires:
  In1/1 -> Out1/1

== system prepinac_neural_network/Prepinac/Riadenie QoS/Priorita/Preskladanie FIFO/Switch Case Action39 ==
  In1 : Inport  OutDataType=sfix(16)  OutScaling=2^0
  Action Port : ActionPort
  Out1 : Outport  OutDataType=sfix(16)  OutScaling=2^0
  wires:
  In1/1 -> Out1/1

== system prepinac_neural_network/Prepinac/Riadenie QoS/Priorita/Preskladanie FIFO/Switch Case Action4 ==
  In1 : Inport  OutDataType=sfix(16)  OutScaling=2^0
  Action Port : ActionPort
  Out1 : Outport  OutDataType=sfix(16)  OutScaling=2^0
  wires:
  In1/1 -> Out1/1

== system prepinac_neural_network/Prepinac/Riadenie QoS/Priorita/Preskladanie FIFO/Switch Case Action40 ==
  In1 : Inport  OutDataType=sfix(16)  OutScaling=2^0
  Action Port : ActionPort
  Out1 : Outport  OutDataType=sfix(16)  OutScaling=2^0
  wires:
  In1/1 -> Out1/1

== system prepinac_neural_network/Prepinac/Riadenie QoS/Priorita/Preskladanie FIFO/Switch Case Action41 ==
  In1 : Inport  OutDataType=sfix(16)  OutScaling=2^0
  Action Port : ActionPort
  Out1 : Outport  OutDataType=sfix(16)  OutScaling=2^0
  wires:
  In1/1 -> Out1/1

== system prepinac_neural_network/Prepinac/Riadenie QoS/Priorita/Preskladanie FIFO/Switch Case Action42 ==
  In1 : Inport  OutDataType=sfix(16)  OutScaling=2^0
  Action Port : ActionPort
  Out1 : Outport  OutDataType=sfix(16)  OutScaling=2^0
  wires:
  In1/1 -> Out1/1

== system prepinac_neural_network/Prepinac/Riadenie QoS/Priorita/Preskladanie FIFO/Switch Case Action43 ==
  In1 : Inport  OutDataType=sfix(16)  OutScaling=2^0
  Action Port : ActionPort
  Out1 : Outport  OutDataType=sfix(16)  OutScaling=2^0
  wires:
  In1/1 -> Out1/1

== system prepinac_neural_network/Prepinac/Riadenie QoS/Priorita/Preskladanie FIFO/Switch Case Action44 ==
  In1 : Inport  OutDataType=sfix(16)  OutScaling=2^0
  Action Port : ActionPort
  Out1 : Outport  OutDataType=sfix(16)  OutScaling=2^0
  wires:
  In1/1 -> Out1/1

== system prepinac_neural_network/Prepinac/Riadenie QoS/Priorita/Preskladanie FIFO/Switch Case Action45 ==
  In1 : Inport  OutDataType=sfix(16)  OutScaling=2^0
  Action Port : ActionPort
  Out1 : Outport  OutDataType=sfix(16)  OutScaling=2^0
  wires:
  In1/1 -> Out1/1

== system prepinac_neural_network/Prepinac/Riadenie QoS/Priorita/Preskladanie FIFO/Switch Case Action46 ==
  In1 : Inport  OutDataType=sfix(16)  OutScaling=2^0
  Action Port : ActionPort
  Out1 : Outport  OutDataType=sfix(16)  OutScaling=2^0
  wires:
  In1/1 -> Out1/1

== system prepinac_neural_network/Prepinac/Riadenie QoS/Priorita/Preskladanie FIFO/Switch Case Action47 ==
  In1 : Inport  OutDataType=sfix(16)  OutScaling=2^0
  Action Port : ActionPort
  Out1 : Outport  OutDataType=sfix(16)  OutScaling=2^0
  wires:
  In1/1 -> Out1/1

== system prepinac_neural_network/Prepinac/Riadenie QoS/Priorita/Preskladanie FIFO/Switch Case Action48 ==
  In1 : Inport  OutDataType=sfix(16)  OutScaling=2^0
  Action Port : ActionPort
  Out1 : Outport  OutDataType=sfix(16)  OutScaling=2^0
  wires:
  In1/1 -> Out1/1

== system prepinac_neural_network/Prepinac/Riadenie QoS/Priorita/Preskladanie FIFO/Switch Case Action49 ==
  In1 : Inport  OutDataType=sfix(16)  OutScaling=2^0
  Action Port : ActionPort
  Out1 : Outport  OutDataType=sfix(16)  OutScaling=2^0
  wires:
  In1/1 -> Out1/1

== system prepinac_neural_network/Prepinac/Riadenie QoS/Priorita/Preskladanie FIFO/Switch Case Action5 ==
  In1 : Inport  OutDataType=sfix(16)  OutScaling=2^0
  Action Port : ActionPort
  Out1 : Outport  OutDataType=sfix(16)  OutScaling=2^0
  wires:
  In1/1 -> Out1/1

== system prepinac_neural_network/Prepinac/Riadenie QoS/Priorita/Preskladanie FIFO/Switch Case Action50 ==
  In1 : Inport  OutDataType=sfix(16)  OutScaling=2^0
  Action Port : ActionPort
  Out1 : Outport  OutDataType=sfix(16)  OutScaling=2^0
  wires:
  In1/1 -> Out1/1

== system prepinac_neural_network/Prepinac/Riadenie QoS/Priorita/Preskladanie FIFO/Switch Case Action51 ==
  In1 : Inport  OutDataType=sfix(16)  OutScaling=2^0
  Action Port : ActionPort
  Out1 : Outport  OutDataType=sfix(16)  OutScaling=2^0
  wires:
  In1/1 -> Out1/1

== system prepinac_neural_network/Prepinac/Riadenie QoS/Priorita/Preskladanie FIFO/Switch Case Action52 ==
  In1 : Inport  OutDataType=sfix(16)  OutScaling=2^0
  Action Port : ActionPort
  Out1 : Outport  OutDataType=sfix(16)  OutScaling=2^0
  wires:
  In1/1 -> Out1/1

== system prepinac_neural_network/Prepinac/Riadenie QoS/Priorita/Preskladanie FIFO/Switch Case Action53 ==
  In1 : Inport  OutDataType=sfix(16)  OutScaling=2^0
  Action Port : ActionPort
  Out1 : Outport  OutDataType=sfix(16)  OutScaling=2^0
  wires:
  In1/1 -> Out1/1

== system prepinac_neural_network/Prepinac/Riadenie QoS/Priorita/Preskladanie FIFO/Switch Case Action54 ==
  In1 : Inport  OutDataType=sfix(16)  OutScaling=2^0
  Action Port : ActionPort
  Out1 : Outport  OutDataType=sfix(16)  OutScaling=2^0
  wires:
  In1/1 -> Out1/1

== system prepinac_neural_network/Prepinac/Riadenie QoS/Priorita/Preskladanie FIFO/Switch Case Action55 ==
  In1 : Inport  OutDataType=sfix(16)  OutScaling=2^0
  Action Port : ActionPort
  Out1 : Outport  OutDataType=sfix(16)  OutScaling=2^0
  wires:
  In1/1 -> Out1/1

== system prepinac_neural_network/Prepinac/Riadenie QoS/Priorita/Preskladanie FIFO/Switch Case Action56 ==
  In1 : Inport  OutDataType=sfix(16)  OutScaling=2^0
  Action Port : ActionPort
  Out1 : Outport  OutDataType=sfix(16)  OutScaling=2^0
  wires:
  In1/1 -> Out1/1

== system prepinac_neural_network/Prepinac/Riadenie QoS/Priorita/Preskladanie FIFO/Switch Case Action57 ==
  In1 : Inport  OutDataType=sfix(16)  OutScaling=2^0
  Action Port : ActionPort
  Out1 : Outport  OutDataType=sfix(16)  OutScaling=2^0
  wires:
  In1/1 -> Out1/1

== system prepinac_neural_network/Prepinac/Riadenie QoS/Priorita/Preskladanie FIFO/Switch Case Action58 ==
  In1 : Inport  OutDataType=sfix(16)  OutScaling=2^0
  Action Port : ActionPort
  Out1 : Outport  OutDataType=sfix(16)  OutScaling=2^0
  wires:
  In1/1 -> Out1/1

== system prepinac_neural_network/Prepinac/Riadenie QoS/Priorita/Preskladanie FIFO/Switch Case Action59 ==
  In1 : Inport  OutDataType=sfix(16)  OutScaling=2^0
  Action Port : ActionPort
  Out1 : Outport  OutDataType=sfix(16)  OutScaling=2^0
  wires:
  In1/1 -> Out1/1

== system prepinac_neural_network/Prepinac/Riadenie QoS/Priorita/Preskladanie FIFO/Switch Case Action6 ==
  In1 : Inport  OutDataType=sfix(16)  OutScaling=2^0
  Action Port : ActionPort
  Out1 : Outport  OutDataType=sfix(16)  OutScaling=2^0
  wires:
  In1/1 -> Out1/1

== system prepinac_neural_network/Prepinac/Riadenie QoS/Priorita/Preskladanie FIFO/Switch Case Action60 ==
  In1 : Inport  OutDataType=sfix(16)  OutScaling=2^0
  Action Port : ActionPort
  Out1 : Outport  OutDataType=sfix(16)  OutScaling=2^0
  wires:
  In1/1 -> Out1/1

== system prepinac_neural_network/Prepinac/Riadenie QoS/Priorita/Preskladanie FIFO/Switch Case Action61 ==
  In1 : Inport  OutDataType=sfix(16)  OutScaling=2^0
  Action Port : ActionPort
  Out1 : Outport  OutDataType=sfix(16)  OutScaling=2^0
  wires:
  In1/1 -> Out1/1

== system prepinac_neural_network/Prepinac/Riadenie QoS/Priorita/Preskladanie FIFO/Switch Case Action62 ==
  In1 : Inport  OutDataType=sfix(16)  OutScaling=2^0
  Action Port : ActionPort
  Out1 : Outport  OutDataType=sfix(16)  OutScaling=2^0
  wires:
  In1/1 -> Out1/1

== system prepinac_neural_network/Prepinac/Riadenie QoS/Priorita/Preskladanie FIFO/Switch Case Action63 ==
  In1 : Inport  OutDataType=sfix(16)  OutScaling=2^0
  Action Port : ActionPort
  Out1 : Outport  OutDataType=sfix(16)  OutScaling=2^0
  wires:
  In1/1 -> Out1/1

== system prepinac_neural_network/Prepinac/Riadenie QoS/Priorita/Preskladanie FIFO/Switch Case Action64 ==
  In1 : Inport  OutDataType=sfix(16)  OutScaling=2^0
  Action Port : ActionPort
  Out1 : Outport  OutDataType=sfix(16)  OutScaling=2^0
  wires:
  In1/1 -> Out1/1

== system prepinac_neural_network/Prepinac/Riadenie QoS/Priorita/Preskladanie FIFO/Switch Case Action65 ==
  In1 : Inport  OutDataType=sfix(16)  OutScaling=2^0
  Action Port : ActionPort
  Out1 : Outport  OutDataType=sfix(16)  OutScaling=2^0
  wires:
  In1/1 -> Out1/1

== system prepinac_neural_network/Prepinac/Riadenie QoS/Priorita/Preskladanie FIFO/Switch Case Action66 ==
  In1 : Inport  OutDataType=sfix(16)  OutScaling=2^0
  Action Port : ActionPort
  Out1 : Outport  OutDataType=sfix(16)  OutScaling=2^0
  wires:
  In1/1 -> Out1/1

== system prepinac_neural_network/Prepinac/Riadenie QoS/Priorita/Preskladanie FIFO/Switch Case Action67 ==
  In1 : Inport  OutDataType=sfix(16)  OutScaling=2^0
  Action Port : ActionPort
  Out1 : Outport  OutDataType=sfix(16)  OutScaling=2^0
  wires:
  In1/1 -> Out1/1

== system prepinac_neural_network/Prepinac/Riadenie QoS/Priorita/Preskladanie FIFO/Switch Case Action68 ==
  In1 : Inport  OutDataType=sfix(16)  OutScaling=2^0
  Action Port : ActionPort
  Out1 : Outport  OutDataType=sfix(16)  OutScaling=2^0
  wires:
  In1/1 -> Out1/1

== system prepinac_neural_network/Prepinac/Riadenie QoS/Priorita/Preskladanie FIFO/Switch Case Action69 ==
  In1 : Inport  OutDataType=sfix(16)  OutScaling=2^0
  Action Port : ActionPort
  Out1 : Outport  OutDataType=sfix(16)  OutScaling=2^0
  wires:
  In1/1 -> Out1/1

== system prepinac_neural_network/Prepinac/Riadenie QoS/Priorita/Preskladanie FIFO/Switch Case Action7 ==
  In1 : Inport  OutDataType=sfix(16)  OutScaling=2^0
  Action Port : ActionPort
  Out1 : Outport  OutDataType=sfix(16)  OutScaling=2^0
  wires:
  In1/1 -> Out1/1

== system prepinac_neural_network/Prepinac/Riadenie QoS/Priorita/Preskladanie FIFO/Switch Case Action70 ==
  In1 : Inport  OutDataType=sfix(16)  OutScaling=2^0
  Action Port : ActionPort
  Out1 : Outport  OutDataType=sfix(16)  OutScaling=2^0
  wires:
  In1/1 -> Out1/1

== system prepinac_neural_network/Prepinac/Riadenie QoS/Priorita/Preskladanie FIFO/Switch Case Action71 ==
  In1 : Inport  OutDataType=sfix(16)  OutScaling=2^0
  Action Port : ActionPort
  Out1 : Outport  OutDataType=sfix(16)  OutScaling=2^0
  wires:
  In1/1 -> Out1/1

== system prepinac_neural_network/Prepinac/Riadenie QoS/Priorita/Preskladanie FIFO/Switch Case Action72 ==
  In1 : Inport  OutDataType=sfix(16)  OutScaling=2^0
  Action Port : ActionPort
  Out1 : Outport  OutDataType=sfix(16)  OutScaling=2^0
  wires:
  In1/1 -> Out1/1

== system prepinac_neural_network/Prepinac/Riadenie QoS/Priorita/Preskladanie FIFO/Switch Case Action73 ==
  In1 : Inport  OutDataType=sfix(16)  OutScaling=2^0
  Action Port : ActionPort
  Out1 : Outport  OutDataType=sfix(16)  OutScaling=2^0
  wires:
  In1/1 -> Out1/1

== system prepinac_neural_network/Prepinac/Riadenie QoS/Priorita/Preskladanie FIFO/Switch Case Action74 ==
  In1 : Inport  OutDataType=sfix(16)  OutScaling=2^0
  Action Port : ActionPort
  Out1 : Outport  OutDataType=sfix(16)  OutScaling=2^0
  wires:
  In1/1 -> Out1/1

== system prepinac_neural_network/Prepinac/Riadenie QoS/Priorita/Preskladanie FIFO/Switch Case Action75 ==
  In1 : Inport  OutDataType=sfix(16)  OutScaling=2^0
  Action Port : ActionPort
  Out1 : Outport  OutDataType=sfix(16)  OutScaling=2^0
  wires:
  In1/1 -> Out1/1

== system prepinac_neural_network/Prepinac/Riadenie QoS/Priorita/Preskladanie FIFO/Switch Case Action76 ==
  In1 : Inport  OutDataType=sfix(16)  OutScaling=2^0
  Action Port : ActionPort
  Out1 : Outport  OutDataType=sfix(16)  OutScaling=2^0
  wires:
  In1/1 -> Out1/1

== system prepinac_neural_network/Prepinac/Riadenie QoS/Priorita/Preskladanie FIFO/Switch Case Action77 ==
  In1 : Inport  OutDataType=sfix(16)  OutScaling=2^0
  Action Port : ActionPort
  Out1 : Outport  OutDataType=sfix(16)  OutScaling=2^0
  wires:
  In1/1 -> Out1/1

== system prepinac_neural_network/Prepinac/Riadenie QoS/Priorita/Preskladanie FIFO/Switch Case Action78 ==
  In1 : Inport  OutDataType=sfix(16)  OutScaling=2^0
  Action Port : ActionPort
  Out1 : Outport  OutDataType=sfix(16)  OutScaling=2^0
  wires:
  In1/1 -> Out1/1

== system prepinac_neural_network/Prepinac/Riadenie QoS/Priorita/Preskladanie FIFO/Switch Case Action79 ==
  In1 : Inport  OutDataType=sfix(16)  OutScaling=2^0
  Action Port : ActionPort
  Out1 : Outport  OutDataType=sfix(16)  OutScaling=2^0
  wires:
  In1/1 -> Out1/1

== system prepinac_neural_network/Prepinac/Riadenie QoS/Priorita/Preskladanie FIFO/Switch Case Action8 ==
  In1 : Inport  OutDataType=sfix(16)  OutScaling=2^0
  Action Port : ActionPort
  Out1 : Outport  OutDataType=sfix(16)  OutScaling=2^0
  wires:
  In1/1 -> Out1/1

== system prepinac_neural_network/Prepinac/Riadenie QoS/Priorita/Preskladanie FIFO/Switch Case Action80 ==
  In1 : Inport  OutDataType=sfix(16)  OutScaling=2^0
  Action Port : ActionPort
  Out1 : Outport  OutDataType=sfix(16)  OutScaling=2^0
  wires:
  In1/1 -> Out1/1

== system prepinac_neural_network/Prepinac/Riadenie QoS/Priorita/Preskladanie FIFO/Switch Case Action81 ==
  In1 : Inport  OutDataType=sfix(16)  OutScaling=2^0
  Action Port : ActionPort
  Out1 : Outport  OutDataType=sfix(16)  OutScaling=2^0
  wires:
  In1/1 -> Out1/1

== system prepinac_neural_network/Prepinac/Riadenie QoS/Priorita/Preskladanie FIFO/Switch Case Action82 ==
  In1 : Inport  OutDataType=sfix(16)  OutScaling=2^0
  Action Port : ActionPort
  Out1 : Outport  OutDataType=sfix(16)  OutScaling=2^0
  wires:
  In1/1 -> Out1/1

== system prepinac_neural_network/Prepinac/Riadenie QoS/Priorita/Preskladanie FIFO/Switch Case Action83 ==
  In1 : Inport  OutDataType=sfix(16)  OutScaling=2^0
  Action Port : ActionPort
  Out1 : Outport  OutDataType=sfix(16)  OutScaling=2^0
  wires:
  In1/1 -> Out1/1
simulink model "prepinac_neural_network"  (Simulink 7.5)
settings: Solver=ode45  StartTime=0.0  StopTime=20  FixedStep=1  MaxStep=1  RelTol=1e-3
libraries: neural x26, commutil2 x24, dspmtrx3 x22, simulink x21
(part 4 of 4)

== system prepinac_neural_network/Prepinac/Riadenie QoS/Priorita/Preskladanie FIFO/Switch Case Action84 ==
  In1 : Inport  OutDataType=sfix(16)  OutScaling=2^0
  Action Port : ActionPort
  Out1 : Outport  OutDataType=sfix(16)  OutScaling=2^0
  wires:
  In1/1 -> Out1/1

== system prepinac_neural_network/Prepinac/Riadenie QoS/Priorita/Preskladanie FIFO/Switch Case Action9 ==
  In1 : Inport  OutDataType=sfix(16)  OutScaling=2^0
  Action Port : ActionPort
  Out1 : Outport  OutDataType=sfix(16)  OutScaling=2^0
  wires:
  In1/1 -> Out1/1

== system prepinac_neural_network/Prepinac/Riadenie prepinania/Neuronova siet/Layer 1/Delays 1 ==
  "p{1}" : Inport  PortDimensions=8  SampleTime=1  OutDataType=sfix(16)  OutScaling=2^0
  mux : Mux  Inputs=1
  "pd{1,1}" : Outport  OutDataType=sfix(16)  OutScaling=2^0
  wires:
  "p{1}"/1 -> mux/1
  mux/1 -> "pd{1,1}"/1

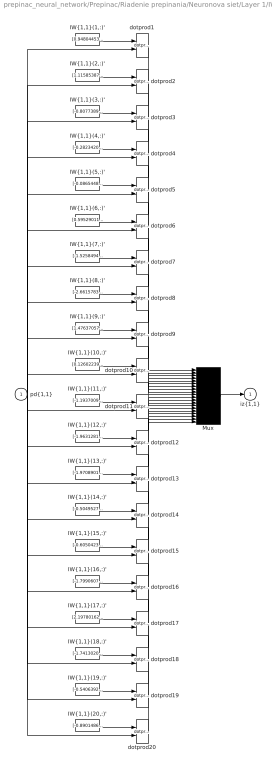
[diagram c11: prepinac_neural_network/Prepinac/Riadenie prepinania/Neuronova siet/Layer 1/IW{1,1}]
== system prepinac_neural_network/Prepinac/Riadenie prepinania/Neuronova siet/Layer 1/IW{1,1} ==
  "pd{1,1}" : Inport  PortDimensions=8  SampleTime=1  OutDataType=sfix(16)  OutScaling=2^0
  "IW{1,1}(1,:)'" : Constant  Value=[0.94804453364749919;-1.8594317269711402;-1.0729065629271457;-1.3780058849473547;-2.4669842737422814;0.70212144865485782;3.514713678555518;0.83069797085676711]  OutDataType=sfix(16)  OutScaling=2^0
  "IW{1,1}(10,:)'" : Constant  Value=[0.12602239488602288;1.3076162417205244;1.0800894882780523;-0.21677233414614011;-1.779946718043993;-1.3915652362391207;1.6141550823181303;3.5135158823222312]  OutDataType=sfix(16)  OutScaling=2^0
  "IW{1,1}(11,:)'" : Constant  Value=[-1.1937009372908192;-2.0138587063466118;0.77065701189562874;2.0134815871226546;0.78231355595112229;0.061597062081779647;1.1414407210040705;2.4956551770423521]  OutDataType=sfix(16)  OutScaling=2^0
  "IW{1,1}(12,:)'" : Constant  Value=[-1.9631281042393292;1.6675889949122598;0.050262722168165172;2.0908483319313418;1.1464876932148951;-2.3486601175418671;-2.070851556420453;-0.79313897114372578]  OutDataType=sfix(16)  OutScaling=2^0
  "IW{1,1}(13,:)'" : Constant  Value=[-1.9708901011163771;1.7454176224830662;1.2306344699102048;0.35198132053751424;2.7662323344871305;-2.8996972324471861;-1.6255257053723235;1.02625279011731]  OutDataType=sfix(16)  OutScaling=2^0
  "IW{1,1}(14,:)'" : Constant  Value=[-0.5049527229227303;1.0798720556329662;0.083032584696078604;0.83166732214833428;2.0657549644510413;-2.2548032506115074;-2.1000958798412284;3.0615368368552982]  OutDataType=sfix(16)  OutScaling=2^0
  "IW{1,1}(15,:)'" : Constant  Value=[-0.60504239213325151;-0.24998659287486677;0.69439749997884725;1.7885666668098783;0.65928385529617139;-3.3370481126829827;-2.2433377745437606;-0.92806233910123503]  OutDataType=sfix(16)  OutScaling=2^0
  "IW{1,1}(16,:)'" : Constant  Value=[-1.7990607204505209;-1.6787233825283236;1.8770682839975936;-1.5839527795873214;3.1467436198884977;-1.6065217602974597;-1.855689118307887;1.4900009662194402]  OutDataType=sfix(16)  OutScaling=2^0
  "IW{1,1}(17,:)'" : Constant  Value=[2.1978016213979825;1.5954010676322765;1.6023672979639849;-2.481901687775721;-1.6115003575793576;-0.51013327732168667;1.4415045326909854;0.21010758819270314]  OutDataType=sfix(16)  OutScaling=2^0
  "IW{1,1}(18,:)'" : Constant  Value=[-1.7413020926788583;-1.5271475509499317;-0.90664414537714255;0.20776426031618583;-0.65787368942962843;1.9319308238957817;0.98438075194839825;-3.247322408338488]  OutDataType=sfix(16)  OutScaling=2^0
  "IW{1,1}(19,:)'" : Constant  Value=[-0.54063925665288104;-0.25550819826406124;0.41004909407822637;-2.3058148110340144;0.21578750159725194;-0.38545022785446292;1.8474041378841259;2.6521108564026075]  OutDataType=sfix(16)  OutScaling=2^0
  "IW{1,1}(2,:)'" : Constant  Value=[1.1158538765759018;1.6266858404367264;1.5393444675683499;1.242754002994082;1.1844130067577403;1.851010581582458;-2.0206900145743663;0.10727312146074208]  OutDataType=sfix(16)  OutScaling=2^0
  "IW{1,1}(20,:)'" : Constant  Value=[-0.89014865848152491;-2.2945730305747594;-1.7422090382078563;-0.22925995317900744;0.70145528555066627;-1.9654718429428524;-2.2884067831667876;2.7906658739254335]  OutDataType=sfix(16)  OutScaling=2^0
  "IW{1,1}(3,:)'" : Constant  Value=[-0.80773894963143755;-1.1914603117543248;2.2532618063257326;1.1280839349638316;2.4781761857354589;0.38353944323500327;0.59250278594362837;2.8056006252869476]  OutDataType=sfix(16)  OutScaling=2^0
  "IW{1,1}(4,:)'" : Constant  Value=[-0.28234209530615384;1.1310033264607993;-0.80672224468423981;-2.3508498782975047;-1.8570500538308783;1.1424498887684249;0.096148040920547503;-1.0987514639045286]  OutDataType=sfix(16)  OutScaling=2^0
  "IW{1,1}(5,:)'" : Constant  Value=[-0.086544899763228045;-0.45518215377763466;1.9449877403534841;0.31460320920140405;0.92502574091064405;1.568077397556358;0.5899278651999329;2.4680180613830824]  OutDataType=sfix(16)  OutScaling=2^0
  "IW{1,1}(6,:)'" : Constant  Value=[0.59529011072265337;-0.55179104106937538;-0.11185579079146968;-0.25021284833906227;1.8209101018383993;2.8516456114473474;-1.4318714962560264;1.5796659478183261]  OutDataType=sfix(16)  OutScaling=2^0
  "IW{1,1}(7,:)'" : Constant  Value=[-1.5258494806788636;0.026005999374503517;0.28640717327234727;1.9070470522266061;1.084561187187435;1.9588529315100993;-0.78403167429170384;-1.8524571998715618]  OutDataType=sfix(16)  OutScaling=2^0
  "IW{1,1}(8,:)'" : Constant  Value=[-2.661578313612595;-1.767497053891105;0.61950963679143312;-1.1643193550666646;1.3326499236007956;0.7491854232716828;-0.006662881670016693;1.4119489652071149]  OutDataType=sfix(16)  OutScaling=2^0
  "IW{1,1}(9,:)'" : Constant  Value=[1.4763705726138863;0.12588040039526732;0.82358088779576566;-2.2126718507313901;1.1047072010619905;0.78715728909938565;-0.93919525918122593;2.5902453396728449]  OutDataType=sfix(16)  OutScaling=2^0
  Mux : Mux  Inputs=20
  dotprod{1..20} (20 alike) : neural/Weight Functions/dotprod  SystemSampleTime=-1
  "iz{1,1}" : Outport  OutDataType=sfix(16)  OutScaling=2^0
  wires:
  "IW{1,1}(1,:)'"/1 -> dotprod1/1
  "pd{1,1}"/1 -> dotprod1/2, dotprod2/2, dotprod3/2, dotprod4/2, dotprod5/2, dotprod6/2, dotprod7/2, dotprod8/2, dotprod9/2, dotprod10/2, dotprod11/2, dotprod12/2, dotprod13/2, dotprod14/2, dotprod15/2, dotprod16/2, dotprod17/2, dotprod18/2, dotprod19/2, dotprod20/2
  dotprod1/1 -> Mux/1
  "IW{1,1}(2,:)'"/1 -> dotprod2/1
  dotprod2/1 -> Mux/2
  "IW{1,1}(3,:)'"/1 -> dotprod3/1
  dotprod3/1 -> Mux/3
  "IW{1,1}(4,:)'"/1 -> dotprod4/1
  dotprod4/1 -> Mux/4
  "IW{1,1}(5,:)'"/1 -> dotprod5/1
  dotprod5/1 -> Mux/5
  "IW{1,1}(6,:)'"/1 -> dotprod6/1
  dotprod6/1 -> Mux/6
  "IW{1,1}(7,:)'"/1 -> dotprod7/1
  dotprod7/1 -> Mux/7
  "IW{1,1}(8,:)'"/1 -> dotprod8/1
  dotprod8/1 -> Mux/8
  "IW{1,1}(9,:)'"/1 -> dotprod9/1
  dotprod9/1 -> Mux/9
  "IW{1,1}(10,:)'"/1 -> dotprod10/1
  dotprod10/1 -> Mux/10
  "IW{1,1}(11,:)'"/1 -> dotprod11/1
  dotprod11/1 -> Mux/11
  "IW{1,1}(12,:)'"/1 -> dotprod12/1
  dotprod12/1 -> Mux/12
  "IW{1,1}(13,:)'"/1 -> dotprod13/1
  dotprod13/1 -> Mux/13
  "IW{1,1}(14,:)'"/1 -> dotprod14/1
  dotprod14/1 -> Mux/14
  "IW{1,1}(15,:)'"/1 -> dotprod15/1
  dotprod15/1 -> Mux/15
  "IW{1,1}(16,:)'"/1 -> dotprod16/1
  dotprod16/1 -> Mux/16
  "IW{1,1}(17,:)'"/1 -> dotprod17/1
  dotprod17/1 -> Mux/17
  "IW{1,1}(18,:)'"/1 -> dotprod18/1
  dotprod18/1 -> Mux/18
  "IW{1,1}(19,:)'"/1 -> dotprod19/1
  dotprod19/1 -> Mux/19
  "IW{1,1}(20,:)'"/1 -> dotprod20/1
  dotprod20/1 -> Mux/20
  Mux/1 -> "iz{1,1}"/1

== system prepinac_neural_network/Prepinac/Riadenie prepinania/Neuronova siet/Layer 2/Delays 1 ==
  "p{2}" : Inport  PortDimensions=20  SampleTime=1  OutDataType=sfix(16)  OutScaling=2^0
  mux : Mux  Inputs=1
  "pd{2,1}" : Outport  OutDataType=sfix(16)  OutScaling=2^0
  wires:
  "p{2}"/1 -> mux/1
  mux/1 -> "pd{2,1}"/1

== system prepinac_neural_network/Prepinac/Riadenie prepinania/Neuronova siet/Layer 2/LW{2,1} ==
  "ad{2,1}" : Inport  PortDimensions=20  SampleTime=1  OutDataType=sfix(16)  OutScaling=2^0
  "IW{2,1}(1,:)'" : Constant  Value=[-1.9119179444036216;-2.373078791022146;0.60738373202331131;1.2031596147557837;1.650166779094064;-0.61111700620688469;1.602365172115449;2.0964047490489826;0.89392049312633381;0.13273338479073937;1.3913968892038715;2.2891791272237718;-0.23815120494133418;-0.48222933409900054;3.8649521025939904;-2.4622077319710907;-0.10192737171225168;1.4793158379234765;1.8000014186485083;-0.41035800899106761]  OutDataType=sfix(16)  OutScaling=2^0
  "IW{2,1}(2,:)'" : Constant  Value=[3.3462217573695292;0.87542497491094939;0.88507703352302736;-0.12973046441643546;-0.2825389610928668;-0.68270667462023238;0.08892628126066339;-0.31439305200266027;-0.87166850868135448;2.0941036573970297;-1.1420437209412284;-1.5639843068026709;2.2535171019561799;1.7970128110373311;-0.20461061435155986;2.7626276160626047;-1.8030962611301231;0.6411944618754456;-0.31167269285990812;-1.7676845629866387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  OutDataType=sfix(16)  OutScaling=2^0
  "IW{2,1}(3,:)'" : Constant  Value=[-1.7458413601934948;-0.52255664191657158;1.6701898242941773;0.36196855071742529;-1.2808707162762596;1.746030323373434;-1.4668077539904545;0.06553056388550127;-0.15618902505513699;-1.1266417904816617;-0.30744433406691973;-1.2566363035551973;-2.2565606398473408;-2.7307012376574908;-2.039533629313488;1.4832872161379234;0.99875474377783657;-1.1060962985218046;0.022412206578230908;2.8463454648581328]  OutDataType=sfix(16)  OutScaling=2^0
  "IW{2,1}(4,:)'" : Constant  Value=[-0.67409789921807395;-0.4420691154690139;-2.7321373042290258;0.11840175378167195;-0.41284706299273355;-1.4467423104670227;0.45770290040484363;0.94717203936514904;-0.55425756363975676;-1.4158324835727851;-0.24758549536653962;-1.0829973589820294;-0.58459000376830361;1.6250624241776253;-1.3689737386809198;-1.9016878840171381;-0.10314160868419416;-0.90485190563303386;-0.47986915801243413;0.1178109252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  OutDataType=sfix(16)  OutScaling=2^0
  Mux : Mux
  dotprod{1..4} (4 alike) : neural/Weight Functions/dotprod  SystemSampleTime=-1
  "lz{2,1}" : Outport  OutDataType=sfix(16)  OutScaling=2^0
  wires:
  "IW{2,1}(1,:)'"/1 -> dotprod1/1
  "ad{2,1}"/1 -> dotprod1/2, dotprod2/2, dotprod3/2, dotprod4/2
  dotprod1/1 -> Mux/1
  "IW{2,1}(2,:)'"/1 -> dotprod2/1
  dotprod2/1 -> Mux/2
  "IW{2,1}(3,:)'"/1 -> dotprod3/1
  dotprod3/1 -> Mux/3
  "IW{2,1}(4,:)'"/1 -> dotprod4/1
  dotprod4/1 -> Mux/4
  Mux/1 -> "lz{2,1}"/1

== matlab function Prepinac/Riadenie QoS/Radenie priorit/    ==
function y = triedenie(x)
tmp=0; 
for j=1:3
for i=1:3
    if x(i)<x(i+1)
    else
       tmp=x(i);
        x(i)=x(i+1);
        x(i+1)=tmp;  
    end;
end;
end;
y=x;

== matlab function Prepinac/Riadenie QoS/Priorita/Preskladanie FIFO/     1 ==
function y = zvysenie_priority(x)
for i=1:3
    for j=1:(4-i)
        if x(i)==x(i+j)
            x(i+j)=x(i+j)+1;
        end;
    end;
end;
y=x;
